VERSION 5.7 ;
  NOWIREEXTENSIONATPIN ON ;
  DIVIDERCHAR "/" ;
  BUSBITCHARS "[]" ;
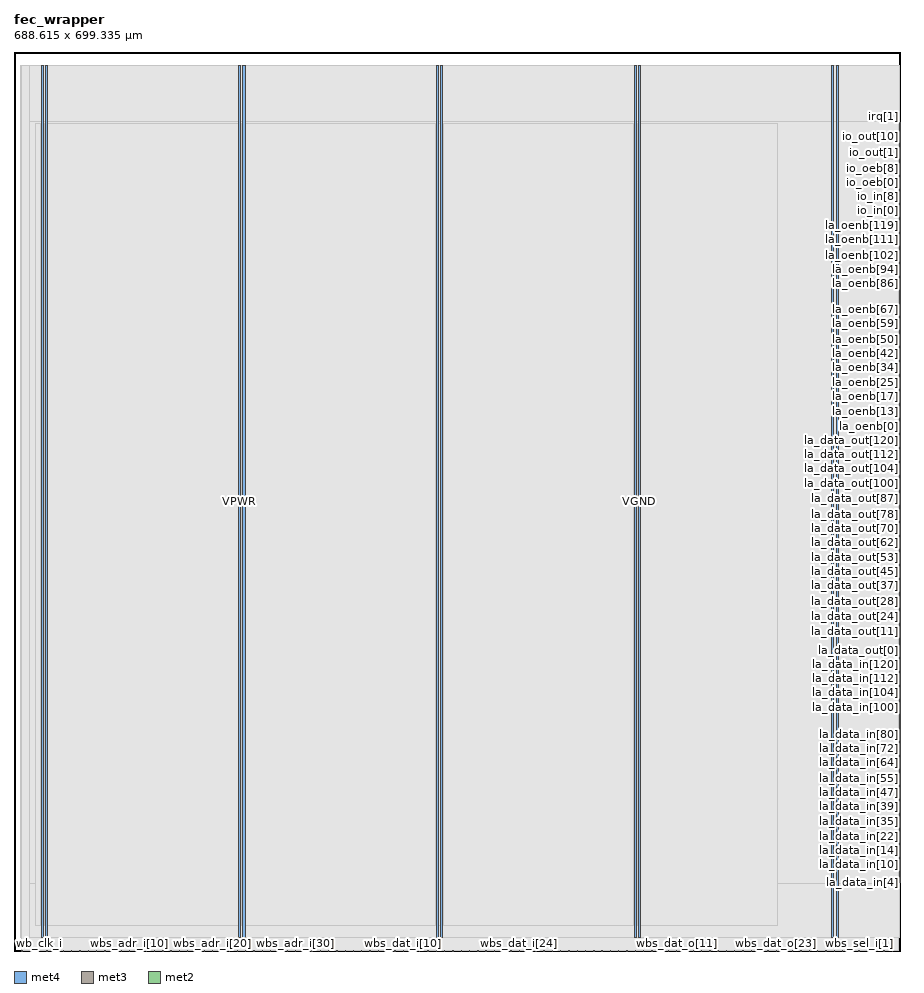
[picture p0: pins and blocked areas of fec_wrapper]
MACRO fec_wrapper
  CLASS BLOCK ;
  FOREIGN fec_wrapper ;
  ORIGIN 0.000 0.000 ;
  SIZE 688.615 BY 699.335 ;
  PIN VGND
    DIRECTION INOUT ;
    USE GROUND ;
    PORT
      LAYER met4 ;
        RECT 24.340 10.640 25.940 688.400 ;
    END
    PORT
      LAYER met4 ;
        RECT 177.940 10.640 179.540 688.400 ;
    END
    PORT
      LAYER met4 ;
        RECT 331.540 10.640 333.140 688.400 ;
    END
    PORT
      LAYER met4 ;
        RECT 485.140 10.640 486.740 688.400 ;
    END
    PORT
      LAYER met4 ;
        RECT 638.740 10.640 640.340 688.400 ;
    END
  END VGND
  PIN VPWR
    DIRECTION INOUT ;
    USE POWER ;
    PORT
      LAYER met4 ;
        RECT 21.040 10.640 22.640 688.400 ;
    END
    PORT
      LAYER met4 ;
        RECT 174.640 10.640 176.240 688.400 ;
    END
    PORT
      LAYER met4 ;
        RECT 328.240 10.640 329.840 688.400 ;
    END
    PORT
      LAYER met4 ;
        RECT 481.840 10.640 483.440 688.400 ;
    END
    PORT
      LAYER met4 ;
        RECT 635.440 10.640 637.040 688.400 ;
    END
  END VPWR
  PIN io_in[0]
    DIRECTION INPUT ;
    USE SIGNAL ;
    ANTENNAGATEAREA 0.647700 ;
    ANTENNADIFFAREA 0.434700 ;
    PORT
      LAYER met3 ;
        RECT 688.015 575.320 688.615 575.920 ;
    END
  END io_in[0]
  PIN io_in[10]
    DIRECTION INPUT ;
    USE SIGNAL ;
    PORT
      LAYER met3 ;
        RECT 688.015 588.920 688.615 589.520 ;
    END
  END io_in[10]
  PIN io_in[11]
    DIRECTION INPUT ;
    USE SIGNAL ;
    PORT
      LAYER met3 ;
        RECT 688.015 590.280 688.615 590.880 ;
    END
  END io_in[11]
  PIN io_in[12]
    DIRECTION INPUT ;
    USE SIGNAL ;
    PORT
      LAYER met3 ;
        RECT 688.015 591.640 688.615 592.240 ;
    END
  END io_in[12]
  PIN io_in[13]
    DIRECTION INPUT ;
    USE SIGNAL ;
    PORT
      LAYER met3 ;
        RECT 688.015 593.000 688.615 593.600 ;
    END
  END io_in[13]
  PIN io_in[14]
    DIRECTION INPUT ;
    USE SIGNAL ;
    PORT
      LAYER met3 ;
        RECT 688.015 594.360 688.615 594.960 ;
    END
  END io_in[14]
  PIN io_in[15]
    DIRECTION INPUT ;
    USE SIGNAL ;
    PORT
      LAYER met3 ;
        RECT 688.015 595.720 688.615 596.320 ;
    END
  END io_in[15]
  PIN io_in[1]
    DIRECTION INPUT ;
    USE SIGNAL ;
    ANTENNAGATEAREA 0.593700 ;
    ANTENNADIFFAREA 0.434700 ;
    PORT
      LAYER met3 ;
        RECT 688.015 576.680 688.615 577.280 ;
    END
  END io_in[1]
  PIN io_in[2]
    DIRECTION INPUT ;
    USE SIGNAL ;
    ANTENNAGATEAREA 0.631200 ;
    ANTENNADIFFAREA 0.434700 ;
    PORT
      LAYER met3 ;
        RECT 688.015 578.040 688.615 578.640 ;
    END
  END io_in[2]
  PIN io_in[3]
    DIRECTION INPUT ;
    USE SIGNAL ;
    PORT
      LAYER met3 ;
        RECT 688.015 579.400 688.615 580.000 ;
    END
  END io_in[3]
  PIN io_in[4]
    DIRECTION INPUT ;
    USE SIGNAL ;
    PORT
      LAYER met3 ;
        RECT 688.015 580.760 688.615 581.360 ;
    END
  END io_in[4]
  PIN io_in[5]
    DIRECTION INPUT ;
    USE SIGNAL ;
    PORT
      LAYER met3 ;
        RECT 688.015 582.120 688.615 582.720 ;
    END
  END io_in[5]
  PIN io_in[6]
    DIRECTION INPUT ;
    USE SIGNAL ;
    PORT
      LAYER met3 ;
        RECT 688.015 583.480 688.615 584.080 ;
    END
  END io_in[6]
  PIN io_in[7]
    DIRECTION INPUT ;
    USE SIGNAL ;
    PORT
      LAYER met3 ;
        RECT 688.015 584.840 688.615 585.440 ;
    END
  END io_in[7]
  PIN io_in[8]
    DIRECTION INPUT ;
    USE SIGNAL ;
    PORT
      LAYER met3 ;
        RECT 688.015 586.200 688.615 586.800 ;
    END
  END io_in[8]
  PIN io_in[9]
    DIRECTION INPUT ;
    USE SIGNAL ;
    PORT
      LAYER met3 ;
        RECT 688.015 587.560 688.615 588.160 ;
    END
  END io_in[9]
  PIN io_oeb[0]
    DIRECTION OUTPUT ;
    USE SIGNAL ;
    PORT
      LAYER met3 ;
        RECT 688.015 597.080 688.615 597.680 ;
    END
  END io_oeb[0]
  PIN io_oeb[10]
    DIRECTION OUTPUT ;
    USE SIGNAL ;
    PORT
      LAYER met3 ;
        RECT 688.015 610.680 688.615 611.280 ;
    END
  END io_oeb[10]
  PIN io_oeb[11]
    DIRECTION OUTPUT ;
    USE SIGNAL ;
    PORT
      LAYER met3 ;
        RECT 688.015 612.040 688.615 612.640 ;
    END
  END io_oeb[11]
  PIN io_oeb[12]
    DIRECTION OUTPUT ;
    USE SIGNAL ;
    PORT
      LAYER met3 ;
        RECT 688.015 613.400 688.615 614.000 ;
    END
  END io_oeb[12]
  PIN io_oeb[13]
    DIRECTION OUTPUT ;
    USE SIGNAL ;
    PORT
      LAYER met3 ;
        RECT 688.015 614.760 688.615 615.360 ;
    END
  END io_oeb[13]
  PIN io_oeb[14]
    DIRECTION OUTPUT ;
    USE SIGNAL ;
    PORT
      LAYER met3 ;
        RECT 688.015 616.120 688.615 616.720 ;
    END
  END io_oeb[14]
  PIN io_oeb[15]
    DIRECTION OUTPUT ;
    USE SIGNAL ;
    PORT
      LAYER met3 ;
        RECT 688.015 617.480 688.615 618.080 ;
    END
  END io_oeb[15]
  PIN io_oeb[1]
    DIRECTION OUTPUT ;
    USE SIGNAL ;
    PORT
      LAYER met3 ;
        RECT 688.015 598.440 688.615 599.040 ;
    END
  END io_oeb[1]
  PIN io_oeb[2]
    DIRECTION OUTPUT ;
    USE SIGNAL ;
    PORT
      LAYER met3 ;
        RECT 688.015 599.800 688.615 600.400 ;
    END
  END io_oeb[2]
  PIN io_oeb[3]
    DIRECTION OUTPUT ;
    USE SIGNAL ;
    PORT
      LAYER met3 ;
        RECT 688.015 601.160 688.615 601.760 ;
    END
  END io_oeb[3]
  PIN io_oeb[4]
    DIRECTION OUTPUT ;
    USE SIGNAL ;
    PORT
      LAYER met3 ;
        RECT 688.015 602.520 688.615 603.120 ;
    END
  END io_oeb[4]
  PIN io_oeb[5]
    DIRECTION OUTPUT ;
    USE SIGNAL ;
    PORT
      LAYER met3 ;
        RECT 688.015 603.880 688.615 604.480 ;
    END
  END io_oeb[5]
  PIN io_oeb[6]
    DIRECTION OUTPUT ;
    USE SIGNAL ;
    PORT
      LAYER met3 ;
        RECT 688.015 605.240 688.615 605.840 ;
    END
  END io_oeb[6]
  PIN io_oeb[7]
    DIRECTION OUTPUT ;
    USE SIGNAL ;
    PORT
      LAYER met3 ;
        RECT 688.015 606.600 688.615 607.200 ;
    END
  END io_oeb[7]
  PIN io_oeb[8]
    DIRECTION OUTPUT ;
    USE SIGNAL ;
    PORT
      LAYER met3 ;
        RECT 688.015 607.960 688.615 608.560 ;
    END
  END io_oeb[8]
  PIN io_oeb[9]
    DIRECTION OUTPUT ;
    USE SIGNAL ;
    PORT
      LAYER met3 ;
        RECT 688.015 609.320 688.615 609.920 ;
    END
  END io_oeb[9]
  PIN io_out[0]
    DIRECTION OUTPUT ;
    USE SIGNAL ;
    ANTENNADIFFAREA 2.673000 ;
    PORT
      LAYER met3 ;
        RECT 688.015 618.840 688.615 619.440 ;
    END
  END io_out[0]
  PIN io_out[10]
    DIRECTION OUTPUT ;
    USE SIGNAL ;
    PORT
      LAYER met3 ;
        RECT 688.015 632.440 688.615 633.040 ;
    END
  END io_out[10]
  PIN io_out[11]
    DIRECTION OUTPUT ;
    USE SIGNAL ;
    PORT
      LAYER met3 ;
        RECT 688.015 633.800 688.615 634.400 ;
    END
  END io_out[11]
  PIN io_out[12]
    DIRECTION OUTPUT ;
    USE SIGNAL ;
    PORT
      LAYER met3 ;
        RECT 688.015 635.160 688.615 635.760 ;
    END
  END io_out[12]
  PIN io_out[13]
    DIRECTION OUTPUT ;
    USE SIGNAL ;
    PORT
      LAYER met3 ;
        RECT 688.015 636.520 688.615 637.120 ;
    END
  END io_out[13]
  PIN io_out[14]
    DIRECTION OUTPUT ;
    USE SIGNAL ;
    PORT
      LAYER met3 ;
        RECT 688.015 637.880 688.615 638.480 ;
    END
  END io_out[14]
  PIN io_out[15]
    DIRECTION OUTPUT ;
    USE SIGNAL ;
    PORT
      LAYER met3 ;
        RECT 688.015 639.240 688.615 639.840 ;
    END
  END io_out[15]
  PIN io_out[1]
    DIRECTION OUTPUT ;
    USE SIGNAL ;
    ANTENNADIFFAREA 2.673000 ;
    PORT
      LAYER met3 ;
        RECT 688.015 620.200 688.615 620.800 ;
    END
  END io_out[1]
  PIN io_out[2]
    DIRECTION OUTPUT ;
    USE SIGNAL ;
    ANTENNADIFFAREA 2.673000 ;
    PORT
      LAYER met3 ;
        RECT 688.015 621.560 688.615 622.160 ;
    END
  END io_out[2]
  PIN io_out[3]
    DIRECTION OUTPUT ;
    USE SIGNAL ;
    ANTENNADIFFAREA 2.673000 ;
    PORT
      LAYER met3 ;
        RECT 688.015 622.920 688.615 623.520 ;
    END
  END io_out[3]
  PIN io_out[4]
    DIRECTION OUTPUT ;
    USE SIGNAL ;
    PORT
      LAYER met3 ;
        RECT 688.015 624.280 688.615 624.880 ;
    END
  END io_out[4]
  PIN io_out[5]
    DIRECTION OUTPUT ;
    USE SIGNAL ;
    PORT
      LAYER met3 ;
        RECT 688.015 625.640 688.615 626.240 ;
    END
  END io_out[5]
  PIN io_out[6]
    DIRECTION OUTPUT ;
    USE SIGNAL ;
    PORT
      LAYER met3 ;
        RECT 688.015 627.000 688.615 627.600 ;
    END
  END io_out[6]
  PIN io_out[7]
    DIRECTION OUTPUT ;
    USE SIGNAL ;
    PORT
      LAYER met3 ;
        RECT 688.015 628.360 688.615 628.960 ;
    END
  END io_out[7]
  PIN io_out[8]
    DIRECTION OUTPUT ;
    USE SIGNAL ;
    PORT
      LAYER met3 ;
        RECT 688.015 629.720 688.615 630.320 ;
    END
  END io_out[8]
  PIN io_out[9]
    DIRECTION OUTPUT ;
    USE SIGNAL ;
    PORT
      LAYER met3 ;
        RECT 688.015 631.080 688.615 631.680 ;
    END
  END io_out[9]
  PIN irq[0]
    DIRECTION OUTPUT ;
    USE SIGNAL ;
    PORT
      LAYER met3 ;
        RECT 688.015 640.600 688.615 641.200 ;
    END
  END irq[0]
  PIN irq[1]
    DIRECTION OUTPUT ;
    USE SIGNAL ;
    PORT
      LAYER met3 ;
        RECT 688.015 641.960 688.615 642.560 ;
    END
  END irq[1]
  PIN irq[2]
    DIRECTION OUTPUT ;
    USE SIGNAL ;
    PORT
      LAYER met3 ;
        RECT 688.015 643.320 688.615 643.920 ;
    END
  END irq[2]
  PIN la_data_in[0]
    DIRECTION INPUT ;
    USE SIGNAL ;
    PORT
      LAYER met3 ;
        RECT 688.015 53.080 688.615 53.680 ;
    END
  END la_data_in[0]
  PIN la_data_in[100]
    DIRECTION INPUT ;
    USE SIGNAL ;
    PORT
      LAYER met3 ;
        RECT 688.015 189.080 688.615 189.680 ;
    END
  END la_data_in[100]
  PIN la_data_in[101]
    DIRECTION INPUT ;
    USE SIGNAL ;
    PORT
      LAYER met3 ;
        RECT 688.015 190.440 688.615 191.040 ;
    END
  END la_data_in[101]
  PIN la_data_in[102]
    DIRECTION INPUT ;
    USE SIGNAL ;
    PORT
      LAYER met3 ;
        RECT 688.015 191.800 688.615 192.400 ;
    END
  END la_data_in[102]
  PIN la_data_in[103]
    DIRECTION INPUT ;
    USE SIGNAL ;
    PORT
      LAYER met3 ;
        RECT 688.015 193.160 688.615 193.760 ;
    END
  END la_data_in[103]
  PIN la_data_in[104]
    DIRECTION INPUT ;
    USE SIGNAL ;
    PORT
      LAYER met3 ;
        RECT 688.015 194.520 688.615 195.120 ;
    END
  END la_data_in[104]
  PIN la_data_in[105]
    DIRECTION INPUT ;
    USE SIGNAL ;
    PORT
      LAYER met3 ;
        RECT 688.015 195.880 688.615 196.480 ;
    END
  END la_data_in[105]
  PIN la_data_in[106]
    DIRECTION INPUT ;
    USE SIGNAL ;
    PORT
      LAYER met3 ;
        RECT 688.015 197.240 688.615 197.840 ;
    END
  END la_data_in[106]
  PIN la_data_in[107]
    DIRECTION INPUT ;
    USE SIGNAL ;
    PORT
      LAYER met3 ;
        RECT 688.015 198.600 688.615 199.200 ;
    END
  END la_data_in[107]
  PIN la_data_in[108]
    DIRECTION INPUT ;
    USE SIGNAL ;
    PORT
      LAYER met3 ;
        RECT 688.015 199.960 688.615 200.560 ;
    END
  END la_data_in[108]
  PIN la_data_in[109]
    DIRECTION INPUT ;
    USE SIGNAL ;
    PORT
      LAYER met3 ;
        RECT 688.015 201.320 688.615 201.920 ;
    END
  END la_data_in[109]
  PIN la_data_in[10]
    DIRECTION INPUT ;
    USE SIGNAL ;
    PORT
      LAYER met3 ;
        RECT 688.015 66.680 688.615 67.280 ;
    END
  END la_data_in[10]
  PIN la_data_in[110]
    DIRECTION INPUT ;
    USE SIGNAL ;
    PORT
      LAYER met3 ;
        RECT 688.015 202.680 688.615 203.280 ;
    END
  END la_data_in[110]
  PIN la_data_in[111]
    DIRECTION INPUT ;
    USE SIGNAL ;
    PORT
      LAYER met3 ;
        RECT 688.015 204.040 688.615 204.640 ;
    END
  END la_data_in[111]
  PIN la_data_in[112]
    DIRECTION INPUT ;
    USE SIGNAL ;
    PORT
      LAYER met3 ;
        RECT 688.015 205.400 688.615 206.000 ;
    END
  END la_data_in[112]
  PIN la_data_in[113]
    DIRECTION INPUT ;
    USE SIGNAL ;
    PORT
      LAYER met3 ;
        RECT 688.015 206.760 688.615 207.360 ;
    END
  END la_data_in[113]
  PIN la_data_in[114]
    DIRECTION INPUT ;
    USE SIGNAL ;
    PORT
      LAYER met3 ;
        RECT 688.015 208.120 688.615 208.720 ;
    END
  END la_data_in[114]
  PIN la_data_in[115]
    DIRECTION INPUT ;
    USE SIGNAL ;
    PORT
      LAYER met3 ;
        RECT 688.015 209.480 688.615 210.080 ;
    END
  END la_data_in[115]
  PIN la_data_in[116]
    DIRECTION INPUT ;
    USE SIGNAL ;
    PORT
      LAYER met3 ;
        RECT 688.015 210.840 688.615 211.440 ;
    END
  END la_data_in[116]
  PIN la_data_in[117]
    DIRECTION INPUT ;
    USE SIGNAL ;
    PORT
      LAYER met3 ;
        RECT 688.015 212.200 688.615 212.800 ;
    END
  END la_data_in[117]
  PIN la_data_in[118]
    DIRECTION INPUT ;
    USE SIGNAL ;
    PORT
      LAYER met3 ;
        RECT 688.015 213.560 688.615 214.160 ;
    END
  END la_data_in[118]
  PIN la_data_in[119]
    DIRECTION INPUT ;
    USE SIGNAL ;
    PORT
      LAYER met3 ;
        RECT 688.015 214.920 688.615 215.520 ;
    END
  END la_data_in[119]
  PIN la_data_in[11]
    DIRECTION INPUT ;
    USE SIGNAL ;
    PORT
      LAYER met3 ;
        RECT 688.015 68.040 688.615 68.640 ;
    END
  END la_data_in[11]
  PIN la_data_in[120]
    DIRECTION INPUT ;
    USE SIGNAL ;
    PORT
      LAYER met3 ;
        RECT 688.015 216.280 688.615 216.880 ;
    END
  END la_data_in[120]
  PIN la_data_in[121]
    DIRECTION INPUT ;
    USE SIGNAL ;
    PORT
      LAYER met3 ;
        RECT 688.015 217.640 688.615 218.240 ;
    END
  END la_data_in[121]
  PIN la_data_in[122]
    DIRECTION INPUT ;
    USE SIGNAL ;
    PORT
      LAYER met3 ;
        RECT 688.015 219.000 688.615 219.600 ;
    END
  END la_data_in[122]
  PIN la_data_in[123]
    DIRECTION INPUT ;
    USE SIGNAL ;
    PORT
      LAYER met3 ;
        RECT 688.015 220.360 688.615 220.960 ;
    END
  END la_data_in[123]
  PIN la_data_in[124]
    DIRECTION INPUT ;
    USE SIGNAL ;
    PORT
      LAYER met3 ;
        RECT 688.015 221.720 688.615 222.320 ;
    END
  END la_data_in[124]
  PIN la_data_in[125]
    DIRECTION INPUT ;
    USE SIGNAL ;
    PORT
      LAYER met3 ;
        RECT 688.015 223.080 688.615 223.680 ;
    END
  END la_data_in[125]
  PIN la_data_in[126]
    DIRECTION INPUT ;
    USE SIGNAL ;
    PORT
      LAYER met3 ;
        RECT 688.015 224.440 688.615 225.040 ;
    END
  END la_data_in[126]
  PIN la_data_in[127]
    DIRECTION INPUT ;
    USE SIGNAL ;
    PORT
      LAYER met3 ;
        RECT 688.015 225.800 688.615 226.400 ;
    END
  END la_data_in[127]
  PIN la_data_in[12]
    DIRECTION INPUT ;
    USE SIGNAL ;
    PORT
      LAYER met3 ;
        RECT 688.015 69.400 688.615 70.000 ;
    END
  END la_data_in[12]
  PIN la_data_in[13]
    DIRECTION INPUT ;
    USE SIGNAL ;
    PORT
      LAYER met3 ;
        RECT 688.015 70.760 688.615 71.360 ;
    END
  END la_data_in[13]
  PIN la_data_in[14]
    DIRECTION INPUT ;
    USE SIGNAL ;
    PORT
      LAYER met3 ;
        RECT 688.015 72.120 688.615 72.720 ;
    END
  END la_data_in[14]
  PIN la_data_in[15]
    DIRECTION INPUT ;
    USE SIGNAL ;
    PORT
      LAYER met3 ;
        RECT 688.015 73.480 688.615 74.080 ;
    END
  END la_data_in[15]
  PIN la_data_in[16]
    DIRECTION INPUT ;
    USE SIGNAL ;
    PORT
      LAYER met3 ;
        RECT 688.015 74.840 688.615 75.440 ;
    END
  END la_data_in[16]
  PIN la_data_in[17]
    DIRECTION INPUT ;
    USE SIGNAL ;
    PORT
      LAYER met3 ;
        RECT 688.015 76.200 688.615 76.800 ;
    END
  END la_data_in[17]
  PIN la_data_in[18]
    DIRECTION INPUT ;
    USE SIGNAL ;
    PORT
      LAYER met3 ;
        RECT 688.015 77.560 688.615 78.160 ;
    END
  END la_data_in[18]
  PIN la_data_in[19]
    DIRECTION INPUT ;
    USE SIGNAL ;
    PORT
      LAYER met3 ;
        RECT 688.015 78.920 688.615 79.520 ;
    END
  END la_data_in[19]
  PIN la_data_in[1]
    DIRECTION INPUT ;
    USE SIGNAL ;
    PORT
      LAYER met3 ;
        RECT 688.015 54.440 688.615 55.040 ;
    END
  END la_data_in[1]
  PIN la_data_in[20]
    DIRECTION INPUT ;
    USE SIGNAL ;
    PORT
      LAYER met3 ;
        RECT 688.015 80.280 688.615 80.880 ;
    END
  END la_data_in[20]
  PIN la_data_in[21]
    DIRECTION INPUT ;
    USE SIGNAL ;
    PORT
      LAYER met3 ;
        RECT 688.015 81.640 688.615 82.240 ;
    END
  END la_data_in[21]
  PIN la_data_in[22]
    DIRECTION INPUT ;
    USE SIGNAL ;
    PORT
      LAYER met3 ;
        RECT 688.015 83.000 688.615 83.600 ;
    END
  END la_data_in[22]
  PIN la_data_in[23]
    DIRECTION INPUT ;
    USE SIGNAL ;
    PORT
      LAYER met3 ;
        RECT 688.015 84.360 688.615 84.960 ;
    END
  END la_data_in[23]
  PIN la_data_in[24]
    DIRECTION INPUT ;
    USE SIGNAL ;
    PORT
      LAYER met3 ;
        RECT 688.015 85.720 688.615 86.320 ;
    END
  END la_data_in[24]
  PIN la_data_in[25]
    DIRECTION INPUT ;
    USE SIGNAL ;
    PORT
      LAYER met3 ;
        RECT 688.015 87.080 688.615 87.680 ;
    END
  END la_data_in[25]
  PIN la_data_in[26]
    DIRECTION INPUT ;
    USE SIGNAL ;
    PORT
      LAYER met3 ;
        RECT 688.015 88.440 688.615 89.040 ;
    END
  END la_data_in[26]
  PIN la_data_in[27]
    DIRECTION INPUT ;
    USE SIGNAL ;
    PORT
      LAYER met3 ;
        RECT 688.015 89.800 688.615 90.400 ;
    END
  END la_data_in[27]
  PIN la_data_in[28]
    DIRECTION INPUT ;
    USE SIGNAL ;
    PORT
      LAYER met3 ;
        RECT 688.015 91.160 688.615 91.760 ;
    END
  END la_data_in[28]
  PIN la_data_in[29]
    DIRECTION INPUT ;
    USE SIGNAL ;
    PORT
      LAYER met3 ;
        RECT 688.015 92.520 688.615 93.120 ;
    END
  END la_data_in[29]
  PIN la_data_in[2]
    DIRECTION INPUT ;
    USE SIGNAL ;
    PORT
      LAYER met3 ;
        RECT 688.015 55.800 688.615 56.400 ;
    END
  END la_data_in[2]
  PIN la_data_in[30]
    DIRECTION INPUT ;
    USE SIGNAL ;
    PORT
      LAYER met3 ;
        RECT 688.015 93.880 688.615 94.480 ;
    END
  END la_data_in[30]
  PIN la_data_in[31]
    DIRECTION INPUT ;
    USE SIGNAL ;
    PORT
      LAYER met3 ;
        RECT 688.015 95.240 688.615 95.840 ;
    END
  END la_data_in[31]
  PIN la_data_in[32]
    DIRECTION INPUT ;
    USE SIGNAL ;
    PORT
      LAYER met3 ;
        RECT 688.015 96.600 688.615 97.200 ;
    END
  END la_data_in[32]
  PIN la_data_in[33]
    DIRECTION INPUT ;
    USE SIGNAL ;
    PORT
      LAYER met3 ;
        RECT 688.015 97.960 688.615 98.560 ;
    END
  END la_data_in[33]
  PIN la_data_in[34]
    DIRECTION INPUT ;
    USE SIGNAL ;
    PORT
      LAYER met3 ;
        RECT 688.015 99.320 688.615 99.920 ;
    END
  END la_data_in[34]
  PIN la_data_in[35]
    DIRECTION INPUT ;
    USE SIGNAL ;
    PORT
      LAYER met3 ;
        RECT 688.015 100.680 688.615 101.280 ;
    END
  END la_data_in[35]
  PIN la_data_in[36]
    DIRECTION INPUT ;
    USE SIGNAL ;
    PORT
      LAYER met3 ;
        RECT 688.015 102.040 688.615 102.640 ;
    END
  END la_data_in[36]
  PIN la_data_in[37]
    DIRECTION INPUT ;
    USE SIGNAL ;
    PORT
      LAYER met3 ;
        RECT 688.015 103.400 688.615 104.000 ;
    END
  END la_data_in[37]
  PIN la_data_in[38]
    DIRECTION INPUT ;
    USE SIGNAL ;
    PORT
      LAYER met3 ;
        RECT 688.015 104.760 688.615 105.360 ;
    END
  END la_data_in[38]
  PIN la_data_in[39]
    DIRECTION INPUT ;
    USE SIGNAL ;
    PORT
      LAYER met3 ;
        RECT 688.015 106.120 688.615 106.720 ;
    END
  END la_data_in[39]
  PIN la_data_in[3]
    DIRECTION INPUT ;
    USE SIGNAL ;
    PORT
      LAYER met3 ;
        RECT 688.015 57.160 688.615 57.760 ;
    END
  END la_data_in[3]
  PIN la_data_in[40]
    DIRECTION INPUT ;
    USE SIGNAL ;
    PORT
      LAYER met3 ;
        RECT 688.015 107.480 688.615 108.080 ;
    END
  END la_data_in[40]
  PIN la_data_in[41]
    DIRECTION INPUT ;
    USE SIGNAL ;
    PORT
      LAYER met3 ;
        RECT 688.015 108.840 688.615 109.440 ;
    END
  END la_data_in[41]
  PIN la_data_in[42]
    DIRECTION INPUT ;
    USE SIGNAL ;
    PORT
      LAYER met3 ;
        RECT 688.015 110.200 688.615 110.800 ;
    END
  END la_data_in[42]
  PIN la_data_in[43]
    DIRECTION INPUT ;
    USE SIGNAL ;
    PORT
      LAYER met3 ;
        RECT 688.015 111.560 688.615 112.160 ;
    END
  END la_data_in[43]
  PIN la_data_in[44]
    DIRECTION INPUT ;
    USE SIGNAL ;
    PORT
      LAYER met3 ;
        RECT 688.015 112.920 688.615 113.520 ;
    END
  END la_data_in[44]
  PIN la_data_in[45]
    DIRECTION INPUT ;
    USE SIGNAL ;
    PORT
      LAYER met3 ;
        RECT 688.015 114.280 688.615 114.880 ;
    END
  END la_data_in[45]
  PIN la_data_in[46]
    DIRECTION INPUT ;
    USE SIGNAL ;
    PORT
      LAYER met3 ;
        RECT 688.015 115.640 688.615 116.240 ;
    END
  END la_data_in[46]
  PIN la_data_in[47]
    DIRECTION INPUT ;
    USE SIGNAL ;
    PORT
      LAYER met3 ;
        RECT 688.015 117.000 688.615 117.600 ;
    END
  END la_data_in[47]
  PIN la_data_in[48]
    DIRECTION INPUT ;
    USE SIGNAL ;
    PORT
      LAYER met3 ;
        RECT 688.015 118.360 688.615 118.960 ;
    END
  END la_data_in[48]
  PIN la_data_in[49]
    DIRECTION INPUT ;
    USE SIGNAL ;
    PORT
      LAYER met3 ;
        RECT 688.015 119.720 688.615 120.320 ;
    END
  END la_data_in[49]
  PIN la_data_in[4]
    DIRECTION INPUT ;
    USE SIGNAL ;
    PORT
      LAYER met3 ;
        RECT 688.015 58.520 688.615 59.120 ;
    END
  END la_data_in[4]
  PIN la_data_in[50]
    DIRECTION INPUT ;
    USE SIGNAL ;
    PORT
      LAYER met3 ;
        RECT 688.015 121.080 688.615 121.680 ;
    END
  END la_data_in[50]
  PIN la_data_in[51]
    DIRECTION INPUT ;
    USE SIGNAL ;
    PORT
      LAYER met3 ;
        RECT 688.015 122.440 688.615 123.040 ;
    END
  END la_data_in[51]
  PIN la_data_in[52]
    DIRECTION INPUT ;
    USE SIGNAL ;
    PORT
      LAYER met3 ;
        RECT 688.015 123.800 688.615 124.400 ;
    END
  END la_data_in[52]
  PIN la_data_in[53]
    DIRECTION INPUT ;
    USE SIGNAL ;
    PORT
      LAYER met3 ;
        RECT 688.015 125.160 688.615 125.760 ;
    END
  END la_data_in[53]
  PIN la_data_in[54]
    DIRECTION INPUT ;
    USE SIGNAL ;
    PORT
      LAYER met3 ;
        RECT 688.015 126.520 688.615 127.120 ;
    END
  END la_data_in[54]
  PIN la_data_in[55]
    DIRECTION INPUT ;
    USE SIGNAL ;
    PORT
      LAYER met3 ;
        RECT 688.015 127.880 688.615 128.480 ;
    END
  END la_data_in[55]
  PIN la_data_in[56]
    DIRECTION INPUT ;
    USE SIGNAL ;
    PORT
      LAYER met3 ;
        RECT 688.015 129.240 688.615 129.840 ;
    END
  END la_data_in[56]
  PIN la_data_in[57]
    DIRECTION INPUT ;
    USE SIGNAL ;
    PORT
      LAYER met3 ;
        RECT 688.015 130.600 688.615 131.200 ;
    END
  END la_data_in[57]
  PIN la_data_in[58]
    DIRECTION INPUT ;
    USE SIGNAL ;
    PORT
      LAYER met3 ;
        RECT 688.015 131.960 688.615 132.560 ;
    END
  END la_data_in[58]
  PIN la_data_in[59]
    DIRECTION INPUT ;
    USE SIGNAL ;
    PORT
      LAYER met3 ;
        RECT 688.015 133.320 688.615 133.920 ;
    END
  END la_data_in[59]
  PIN la_data_in[5]
    DIRECTION INPUT ;
    USE SIGNAL ;
    PORT
      LAYER met3 ;
        RECT 688.015 59.880 688.615 60.480 ;
    END
  END la_data_in[5]
  PIN la_data_in[60]
    DIRECTION INPUT ;
    USE SIGNAL ;
    PORT
      LAYER met3 ;
        RECT 688.015 134.680 688.615 135.280 ;
    END
  END la_data_in[60]
  PIN la_data_in[61]
    DIRECTION INPUT ;
    USE SIGNAL ;
    PORT
      LAYER met3 ;
        RECT 688.015 136.040 688.615 136.640 ;
    END
  END la_data_in[61]
  PIN la_data_in[62]
    DIRECTION INPUT ;
    USE SIGNAL ;
    PORT
      LAYER met3 ;
        RECT 688.015 137.400 688.615 138.000 ;
    END
  END la_data_in[62]
  PIN la_data_in[63]
    DIRECTION INPUT ;
    USE SIGNAL ;
    PORT
      LAYER met3 ;
        RECT 688.015 138.760 688.615 139.360 ;
    END
  END la_data_in[63]
  PIN la_data_in[64]
    DIRECTION INPUT ;
    USE SIGNAL ;
    ANTENNAGATEAREA 0.647700 ;
    ANTENNADIFFAREA 0.434700 ;
    PORT
      LAYER met3 ;
        RECT 688.015 140.120 688.615 140.720 ;
    END
  END la_data_in[64]
  PIN la_data_in[65]
    DIRECTION INPUT ;
    USE SIGNAL ;
    ANTENNAGATEAREA 0.647700 ;
    ANTENNADIFFAREA 0.434700 ;
    PORT
      LAYER met3 ;
        RECT 688.015 141.480 688.615 142.080 ;
    END
  END la_data_in[65]
  PIN la_data_in[66]
    DIRECTION INPUT ;
    USE SIGNAL ;
    PORT
      LAYER met3 ;
        RECT 688.015 142.840 688.615 143.440 ;
    END
  END la_data_in[66]
  PIN la_data_in[67]
    DIRECTION INPUT ;
    USE SIGNAL ;
    PORT
      LAYER met3 ;
        RECT 688.015 144.200 688.615 144.800 ;
    END
  END la_data_in[67]
  PIN la_data_in[68]
    DIRECTION INPUT ;
    USE SIGNAL ;
    PORT
      LAYER met3 ;
        RECT 688.015 145.560 688.615 146.160 ;
    END
  END la_data_in[68]
  PIN la_data_in[69]
    DIRECTION INPUT ;
    USE SIGNAL ;
    PORT
      LAYER met3 ;
        RECT 688.015 146.920 688.615 147.520 ;
    END
  END la_data_in[69]
  PIN la_data_in[6]
    DIRECTION INPUT ;
    USE SIGNAL ;
    PORT
      LAYER met3 ;
        RECT 688.015 61.240 688.615 61.840 ;
    END
  END la_data_in[6]
  PIN la_data_in[70]
    DIRECTION INPUT ;
    USE SIGNAL ;
    PORT
      LAYER met3 ;
        RECT 688.015 148.280 688.615 148.880 ;
    END
  END la_data_in[70]
  PIN la_data_in[71]
    DIRECTION INPUT ;
    USE SIGNAL ;
    PORT
      LAYER met3 ;
        RECT 688.015 149.640 688.615 150.240 ;
    END
  END la_data_in[71]
  PIN la_data_in[72]
    DIRECTION INPUT ;
    USE SIGNAL ;
    PORT
      LAYER met3 ;
        RECT 688.015 151.000 688.615 151.600 ;
    END
  END la_data_in[72]
  PIN la_data_in[73]
    DIRECTION INPUT ;
    USE SIGNAL ;
    PORT
      LAYER met3 ;
        RECT 688.015 152.360 688.615 152.960 ;
    END
  END la_data_in[73]
  PIN la_data_in[74]
    DIRECTION INPUT ;
    USE SIGNAL ;
    PORT
      LAYER met3 ;
        RECT 688.015 153.720 688.615 154.320 ;
    END
  END la_data_in[74]
  PIN la_data_in[75]
    DIRECTION INPUT ;
    USE SIGNAL ;
    PORT
      LAYER met3 ;
        RECT 688.015 155.080 688.615 155.680 ;
    END
  END la_data_in[75]
  PIN la_data_in[76]
    DIRECTION INPUT ;
    USE SIGNAL ;
    PORT
      LAYER met3 ;
        RECT 688.015 156.440 688.615 157.040 ;
    END
  END la_data_in[76]
  PIN la_data_in[77]
    DIRECTION INPUT ;
    USE SIGNAL ;
    PORT
      LAYER met3 ;
        RECT 688.015 157.800 688.615 158.400 ;
    END
  END la_data_in[77]
  PIN la_data_in[78]
    DIRECTION INPUT ;
    USE SIGNAL ;
    PORT
      LAYER met3 ;
        RECT 688.015 159.160 688.615 159.760 ;
    END
  END la_data_in[78]
  PIN la_data_in[79]
    DIRECTION INPUT ;
    USE SIGNAL ;
    PORT
      LAYER met3 ;
        RECT 688.015 160.520 688.615 161.120 ;
    END
  END la_data_in[79]
  PIN la_data_in[7]
    DIRECTION INPUT ;
    USE SIGNAL ;
    PORT
      LAYER met3 ;
        RECT 688.015 62.600 688.615 63.200 ;
    END
  END la_data_in[7]
  PIN la_data_in[80]
    DIRECTION INPUT ;
    USE SIGNAL ;
    PORT
      LAYER met3 ;
        RECT 688.015 161.880 688.615 162.480 ;
    END
  END la_data_in[80]
  PIN la_data_in[81]
    DIRECTION INPUT ;
    USE SIGNAL ;
    PORT
      LAYER met3 ;
        RECT 688.015 163.240 688.615 163.840 ;
    END
  END la_data_in[81]
  PIN la_data_in[82]
    DIRECTION INPUT ;
    USE SIGNAL ;
    PORT
      LAYER met3 ;
        RECT 688.015 164.600 688.615 165.200 ;
    END
  END la_data_in[82]
  PIN la_data_in[83]
    DIRECTION INPUT ;
    USE SIGNAL ;
    PORT
      LAYER met3 ;
        RECT 688.015 165.960 688.615 166.560 ;
    END
  END la_data_in[83]
  PIN la_data_in[84]
    DIRECTION INPUT ;
    USE SIGNAL ;
    PORT
      LAYER met3 ;
        RECT 688.015 167.320 688.615 167.920 ;
    END
  END la_data_in[84]
  PIN la_data_in[85]
    DIRECTION INPUT ;
    USE SIGNAL ;
    PORT
      LAYER met3 ;
        RECT 688.015 168.680 688.615 169.280 ;
    END
  END la_data_in[85]
  PIN la_data_in[86]
    DIRECTION INPUT ;
    USE SIGNAL ;
    PORT
      LAYER met3 ;
        RECT 688.015 170.040 688.615 170.640 ;
    END
  END la_data_in[86]
  PIN la_data_in[87]
    DIRECTION INPUT ;
    USE SIGNAL ;
    PORT
      LAYER met3 ;
        RECT 688.015 171.400 688.615 172.000 ;
    END
  END la_data_in[87]
  PIN la_data_in[88]
    DIRECTION INPUT ;
    USE SIGNAL ;
    PORT
      LAYER met3 ;
        RECT 688.015 172.760 688.615 173.360 ;
    END
  END la_data_in[88]
  PIN la_data_in[89]
    DIRECTION INPUT ;
    USE SIGNAL ;
    PORT
      LAYER met3 ;
        RECT 688.015 174.120 688.615 174.720 ;
    END
  END la_data_in[89]
  PIN la_data_in[8]
    DIRECTION INPUT ;
    USE SIGNAL ;
    PORT
      LAYER met3 ;
        RECT 688.015 63.960 688.615 64.560 ;
    END
  END la_data_in[8]
  PIN la_data_in[90]
    DIRECTION INPUT ;
    USE SIGNAL ;
    PORT
      LAYER met3 ;
        RECT 688.015 175.480 688.615 176.080 ;
    END
  END la_data_in[90]
  PIN la_data_in[91]
    DIRECTION INPUT ;
    USE SIGNAL ;
    PORT
      LAYER met3 ;
        RECT 688.015 176.840 688.615 177.440 ;
    END
  END la_data_in[91]
  PIN la_data_in[92]
    DIRECTION INPUT ;
    USE SIGNAL ;
    PORT
      LAYER met3 ;
        RECT 688.015 178.200 688.615 178.800 ;
    END
  END la_data_in[92]
  PIN la_data_in[93]
    DIRECTION INPUT ;
    USE SIGNAL ;
    PORT
      LAYER met3 ;
        RECT 688.015 179.560 688.615 180.160 ;
    END
  END la_data_in[93]
  PIN la_data_in[94]
    DIRECTION INPUT ;
    USE SIGNAL ;
    PORT
      LAYER met3 ;
        RECT 688.015 180.920 688.615 181.520 ;
    END
  END la_data_in[94]
  PIN la_data_in[95]
    DIRECTION INPUT ;
    USE SIGNAL ;
    PORT
      LAYER met3 ;
        RECT 688.015 182.280 688.615 182.880 ;
    END
  END la_data_in[95]
  PIN la_data_in[96]
    DIRECTION INPUT ;
    USE SIGNAL ;
    PORT
      LAYER met3 ;
        RECT 688.015 183.640 688.615 184.240 ;
    END
  END la_data_in[96]
  PIN la_data_in[97]
    DIRECTION INPUT ;
    USE SIGNAL ;
    PORT
      LAYER met3 ;
        RECT 688.015 185.000 688.615 185.600 ;
    END
  END la_data_in[97]
  PIN la_data_in[98]
    DIRECTION INPUT ;
    USE SIGNAL ;
    PORT
      LAYER met3 ;
        RECT 688.015 186.360 688.615 186.960 ;
    END
  END la_data_in[98]
  PIN la_data_in[99]
    DIRECTION INPUT ;
    USE SIGNAL ;
    PORT
      LAYER met3 ;
        RECT 688.015 187.720 688.615 188.320 ;
    END
  END la_data_in[99]
  PIN la_data_in[9]
    DIRECTION INPUT ;
    USE SIGNAL ;
    PORT
      LAYER met3 ;
        RECT 688.015 65.320 688.615 65.920 ;
    END
  END la_data_in[9]
  PIN la_data_out[0]
    DIRECTION OUTPUT ;
    USE SIGNAL ;
    PORT
      LAYER met3 ;
        RECT 688.015 227.160 688.615 227.760 ;
    END
  END la_data_out[0]
  PIN la_data_out[100]
    DIRECTION OUTPUT ;
    USE SIGNAL ;
    PORT
      LAYER met3 ;
        RECT 688.015 363.160 688.615 363.760 ;
    END
  END la_data_out[100]
  PIN la_data_out[101]
    DIRECTION OUTPUT ;
    USE SIGNAL ;
    PORT
      LAYER met3 ;
        RECT 688.015 364.520 688.615 365.120 ;
    END
  END la_data_out[101]
  PIN la_data_out[102]
    DIRECTION OUTPUT ;
    USE SIGNAL ;
    PORT
      LAYER met3 ;
        RECT 688.015 365.880 688.615 366.480 ;
    END
  END la_data_out[102]
  PIN la_data_out[103]
    DIRECTION OUTPUT ;
    USE SIGNAL ;
    PORT
      LAYER met3 ;
        RECT 688.015 367.240 688.615 367.840 ;
    END
  END la_data_out[103]
  PIN la_data_out[104]
    DIRECTION OUTPUT ;
    USE SIGNAL ;
    PORT
      LAYER met3 ;
        RECT 688.015 368.600 688.615 369.200 ;
    END
  END la_data_out[104]
  PIN la_data_out[105]
    DIRECTION OUTPUT ;
    USE SIGNAL ;
    PORT
      LAYER met3 ;
        RECT 688.015 369.960 688.615 370.560 ;
    END
  END la_data_out[105]
  PIN la_data_out[106]
    DIRECTION OUTPUT ;
    USE SIGNAL ;
    PORT
      LAYER met3 ;
        RECT 688.015 371.320 688.615 371.920 ;
    END
  END la_data_out[106]
  PIN la_data_out[107]
    DIRECTION OUTPUT ;
    USE SIGNAL ;
    PORT
      LAYER met3 ;
        RECT 688.015 372.680 688.615 373.280 ;
    END
  END la_data_out[107]
  PIN la_data_out[108]
    DIRECTION OUTPUT ;
    USE SIGNAL ;
    PORT
      LAYER met3 ;
        RECT 688.015 374.040 688.615 374.640 ;
    END
  END la_data_out[108]
  PIN la_data_out[109]
    DIRECTION OUTPUT ;
    USE SIGNAL ;
    PORT
      LAYER met3 ;
        RECT 688.015 375.400 688.615 376.000 ;
    END
  END la_data_out[109]
  PIN la_data_out[10]
    DIRECTION OUTPUT ;
    USE SIGNAL ;
    PORT
      LAYER met3 ;
        RECT 688.015 240.760 688.615 241.360 ;
    END
  END la_data_out[10]
  PIN la_data_out[110]
    DIRECTION OUTPUT ;
    USE SIGNAL ;
    PORT
      LAYER met3 ;
        RECT 688.015 376.760 688.615 377.360 ;
    END
  END la_data_out[110]
  PIN la_data_out[111]
    DIRECTION OUTPUT ;
    USE SIGNAL ;
    PORT
      LAYER met3 ;
        RECT 688.015 378.120 688.615 378.720 ;
    END
  END la_data_out[111]
  PIN la_data_out[112]
    DIRECTION OUTPUT ;
    USE SIGNAL ;
    PORT
      LAYER met3 ;
        RECT 688.015 379.480 688.615 380.080 ;
    END
  END la_data_out[112]
  PIN la_data_out[113]
    DIRECTION OUTPUT ;
    USE SIGNAL ;
    PORT
      LAYER met3 ;
        RECT 688.015 380.840 688.615 381.440 ;
    END
  END la_data_out[113]
  PIN la_data_out[114]
    DIRECTION OUTPUT ;
    USE SIGNAL ;
    PORT
      LAYER met3 ;
        RECT 688.015 382.200 688.615 382.800 ;
    END
  END la_data_out[114]
  PIN la_data_out[115]
    DIRECTION OUTPUT ;
    USE SIGNAL ;
    PORT
      LAYER met3 ;
        RECT 688.015 383.560 688.615 384.160 ;
    END
  END la_data_out[115]
  PIN la_data_out[116]
    DIRECTION OUTPUT ;
    USE SIGNAL ;
    PORT
      LAYER met3 ;
        RECT 688.015 384.920 688.615 385.520 ;
    END
  END la_data_out[116]
  PIN la_data_out[117]
    DIRECTION OUTPUT ;
    USE SIGNAL ;
    PORT
      LAYER met3 ;
        RECT 688.015 386.280 688.615 386.880 ;
    END
  END la_data_out[117]
  PIN la_data_out[118]
    DIRECTION OUTPUT ;
    USE SIGNAL ;
    PORT
      LAYER met3 ;
        RECT 688.015 387.640 688.615 388.240 ;
    END
  END la_data_out[118]
  PIN la_data_out[119]
    DIRECTION OUTPUT ;
    USE SIGNAL ;
    PORT
      LAYER met3 ;
        RECT 688.015 389.000 688.615 389.600 ;
    END
  END la_data_out[119]
  PIN la_data_out[11]
    DIRECTION OUTPUT ;
    USE SIGNAL ;
    PORT
      LAYER met3 ;
        RECT 688.015 242.120 688.615 242.720 ;
    END
  END la_data_out[11]
  PIN la_data_out[120]
    DIRECTION OUTPUT ;
    USE SIGNAL ;
    PORT
      LAYER met3 ;
        RECT 688.015 390.360 688.615 390.960 ;
    END
  END la_data_out[120]
  PIN la_data_out[121]
    DIRECTION OUTPUT ;
    USE SIGNAL ;
    PORT
      LAYER met3 ;
        RECT 688.015 391.720 688.615 392.320 ;
    END
  END la_data_out[121]
  PIN la_data_out[122]
    DIRECTION OUTPUT ;
    USE SIGNAL ;
    PORT
      LAYER met3 ;
        RECT 688.015 393.080 688.615 393.680 ;
    END
  END la_data_out[122]
  PIN la_data_out[123]
    DIRECTION OUTPUT ;
    USE SIGNAL ;
    PORT
      LAYER met3 ;
        RECT 688.015 394.440 688.615 395.040 ;
    END
  END la_data_out[123]
  PIN la_data_out[124]
    DIRECTION OUTPUT ;
    USE SIGNAL ;
    PORT
      LAYER met3 ;
        RECT 688.015 395.800 688.615 396.400 ;
    END
  END la_data_out[124]
  PIN la_data_out[125]
    DIRECTION OUTPUT ;
    USE SIGNAL ;
    PORT
      LAYER met3 ;
        RECT 688.015 397.160 688.615 397.760 ;
    END
  END la_data_out[125]
  PIN la_data_out[126]
    DIRECTION OUTPUT ;
    USE SIGNAL ;
    PORT
      LAYER met3 ;
        RECT 688.015 398.520 688.615 399.120 ;
    END
  END la_data_out[126]
  PIN la_data_out[127]
    DIRECTION OUTPUT ;
    USE SIGNAL ;
    PORT
      LAYER met3 ;
        RECT 688.015 399.880 688.615 400.480 ;
    END
  END la_data_out[127]
  PIN la_data_out[12]
    DIRECTION OUTPUT ;
    USE SIGNAL ;
    PORT
      LAYER met3 ;
        RECT 688.015 243.480 688.615 244.080 ;
    END
  END la_data_out[12]
  PIN la_data_out[13]
    DIRECTION OUTPUT ;
    USE SIGNAL ;
    PORT
      LAYER met3 ;
        RECT 688.015 244.840 688.615 245.440 ;
    END
  END la_data_out[13]
  PIN la_data_out[14]
    DIRECTION OUTPUT ;
    USE SIGNAL ;
    PORT
      LAYER met3 ;
        RECT 688.015 246.200 688.615 246.800 ;
    END
  END la_data_out[14]
  PIN la_data_out[15]
    DIRECTION OUTPUT ;
    USE SIGNAL ;
    PORT
      LAYER met3 ;
        RECT 688.015 247.560 688.615 248.160 ;
    END
  END la_data_out[15]
  PIN la_data_out[16]
    DIRECTION OUTPUT ;
    USE SIGNAL ;
    PORT
      LAYER met3 ;
        RECT 688.015 248.920 688.615 249.520 ;
    END
  END la_data_out[16]
  PIN la_data_out[17]
    DIRECTION OUTPUT ;
    USE SIGNAL ;
    PORT
      LAYER met3 ;
        RECT 688.015 250.280 688.615 250.880 ;
    END
  END la_data_out[17]
  PIN la_data_out[18]
    DIRECTION OUTPUT ;
    USE SIGNAL ;
    PORT
      LAYER met3 ;
        RECT 688.015 251.640 688.615 252.240 ;
    END
  END la_data_out[18]
  PIN la_data_out[19]
    DIRECTION OUTPUT ;
    USE SIGNAL ;
    PORT
      LAYER met3 ;
        RECT 688.015 253.000 688.615 253.600 ;
    END
  END la_data_out[19]
  PIN la_data_out[1]
    DIRECTION OUTPUT ;
    USE SIGNAL ;
    PORT
      LAYER met3 ;
        RECT 688.015 228.520 688.615 229.120 ;
    END
  END la_data_out[1]
  PIN la_data_out[20]
    DIRECTION OUTPUT ;
    USE SIGNAL ;
    PORT
      LAYER met3 ;
        RECT 688.015 254.360 688.615 254.960 ;
    END
  END la_data_out[20]
  PIN la_data_out[21]
    DIRECTION OUTPUT ;
    USE SIGNAL ;
    PORT
      LAYER met3 ;
        RECT 688.015 255.720 688.615 256.320 ;
    END
  END la_data_out[21]
  PIN la_data_out[22]
    DIRECTION OUTPUT ;
    USE SIGNAL ;
    PORT
      LAYER met3 ;
        RECT 688.015 257.080 688.615 257.680 ;
    END
  END la_data_out[22]
  PIN la_data_out[23]
    DIRECTION OUTPUT ;
    USE SIGNAL ;
    PORT
      LAYER met3 ;
        RECT 688.015 258.440 688.615 259.040 ;
    END
  END la_data_out[23]
  PIN la_data_out[24]
    DIRECTION OUTPUT ;
    USE SIGNAL ;
    PORT
      LAYER met3 ;
        RECT 688.015 259.800 688.615 260.400 ;
    END
  END la_data_out[24]
  PIN la_data_out[25]
    DIRECTION OUTPUT ;
    USE SIGNAL ;
    PORT
      LAYER met3 ;
        RECT 688.015 261.160 688.615 261.760 ;
    END
  END la_data_out[25]
  PIN la_data_out[26]
    DIRECTION OUTPUT ;
    USE SIGNAL ;
    PORT
      LAYER met3 ;
        RECT 688.015 262.520 688.615 263.120 ;
    END
  END la_data_out[26]
  PIN la_data_out[27]
    DIRECTION OUTPUT ;
    USE SIGNAL ;
    PORT
      LAYER met3 ;
        RECT 688.015 263.880 688.615 264.480 ;
    END
  END la_data_out[27]
  PIN la_data_out[28]
    DIRECTION OUTPUT ;
    USE SIGNAL ;
    PORT
      LAYER met3 ;
        RECT 688.015 265.240 688.615 265.840 ;
    END
  END la_data_out[28]
  PIN la_data_out[29]
    DIRECTION OUTPUT ;
    USE SIGNAL ;
    PORT
      LAYER met3 ;
        RECT 688.015 266.600 688.615 267.200 ;
    END
  END la_data_out[29]
  PIN la_data_out[2]
    DIRECTION OUTPUT ;
    USE SIGNAL ;
    PORT
      LAYER met3 ;
        RECT 688.015 229.880 688.615 230.480 ;
    END
  END la_data_out[2]
  PIN la_data_out[30]
    DIRECTION OUTPUT ;
    USE SIGNAL ;
    PORT
      LAYER met3 ;
        RECT 688.015 267.960 688.615 268.560 ;
    END
  END la_data_out[30]
  PIN la_data_out[31]
    DIRECTION OUTPUT ;
    USE SIGNAL ;
    PORT
      LAYER met3 ;
        RECT 688.015 269.320 688.615 269.920 ;
    END
  END la_data_out[31]
  PIN la_data_out[32]
    DIRECTION OUTPUT ;
    USE SIGNAL ;
    PORT
      LAYER met3 ;
        RECT 688.015 270.680 688.615 271.280 ;
    END
  END la_data_out[32]
  PIN la_data_out[33]
    DIRECTION OUTPUT ;
    USE SIGNAL ;
    PORT
      LAYER met3 ;
        RECT 688.015 272.040 688.615 272.640 ;
    END
  END la_data_out[33]
  PIN la_data_out[34]
    DIRECTION OUTPUT ;
    USE SIGNAL ;
    PORT
      LAYER met3 ;
        RECT 688.015 273.400 688.615 274.000 ;
    END
  END la_data_out[34]
  PIN la_data_out[35]
    DIRECTION OUTPUT ;
    USE SIGNAL ;
    PORT
      LAYER met3 ;
        RECT 688.015 274.760 688.615 275.360 ;
    END
  END la_data_out[35]
  PIN la_data_out[36]
    DIRECTION OUTPUT ;
    USE SIGNAL ;
    PORT
      LAYER met3 ;
        RECT 688.015 276.120 688.615 276.720 ;
    END
  END la_data_out[36]
  PIN la_data_out[37]
    DIRECTION OUTPUT ;
    USE SIGNAL ;
    PORT
      LAYER met3 ;
        RECT 688.015 277.480 688.615 278.080 ;
    END
  END la_data_out[37]
  PIN la_data_out[38]
    DIRECTION OUTPUT ;
    USE SIGNAL ;
    PORT
      LAYER met3 ;
        RECT 688.015 278.840 688.615 279.440 ;
    END
  END la_data_out[38]
  PIN la_data_out[39]
    DIRECTION OUTPUT ;
    USE SIGNAL ;
    PORT
      LAYER met3 ;
        RECT 688.015 280.200 688.615 280.800 ;
    END
  END la_data_out[39]
  PIN la_data_out[3]
    DIRECTION OUTPUT ;
    USE SIGNAL ;
    PORT
      LAYER met3 ;
        RECT 688.015 231.240 688.615 231.840 ;
    END
  END la_data_out[3]
  PIN la_data_out[40]
    DIRECTION OUTPUT ;
    USE SIGNAL ;
    PORT
      LAYER met3 ;
        RECT 688.015 281.560 688.615 282.160 ;
    END
  END la_data_out[40]
  PIN la_data_out[41]
    DIRECTION OUTPUT ;
    USE SIGNAL ;
    PORT
      LAYER met3 ;
        RECT 688.015 282.920 688.615 283.520 ;
    END
  END la_data_out[41]
  PIN la_data_out[42]
    DIRECTION OUTPUT ;
    USE SIGNAL ;
    PORT
      LAYER met3 ;
        RECT 688.015 284.280 688.615 284.880 ;
    END
  END la_data_out[42]
  PIN la_data_out[43]
    DIRECTION OUTPUT ;
    USE SIGNAL ;
    PORT
      LAYER met3 ;
        RECT 688.015 285.640 688.615 286.240 ;
    END
  END la_data_out[43]
  PIN la_data_out[44]
    DIRECTION OUTPUT ;
    USE SIGNAL ;
    PORT
      LAYER met3 ;
        RECT 688.015 287.000 688.615 287.600 ;
    END
  END la_data_out[44]
  PIN la_data_out[45]
    DIRECTION OUTPUT ;
    USE SIGNAL ;
    PORT
      LAYER met3 ;
        RECT 688.015 288.360 688.615 288.960 ;
    END
  END la_data_out[45]
  PIN la_data_out[46]
    DIRECTION OUTPUT ;
    USE SIGNAL ;
    PORT
      LAYER met3 ;
        RECT 688.015 289.720 688.615 290.320 ;
    END
  END la_data_out[46]
  PIN la_data_out[47]
    DIRECTION OUTPUT ;
    USE SIGNAL ;
    PORT
      LAYER met3 ;
        RECT 688.015 291.080 688.615 291.680 ;
    END
  END la_data_out[47]
  PIN la_data_out[48]
    DIRECTION OUTPUT ;
    USE SIGNAL ;
    PORT
      LAYER met3 ;
        RECT 688.015 292.440 688.615 293.040 ;
    END
  END la_data_out[48]
  PIN la_data_out[49]
    DIRECTION OUTPUT ;
    USE SIGNAL ;
    PORT
      LAYER met3 ;
        RECT 688.015 293.800 688.615 294.400 ;
    END
  END la_data_out[49]
  PIN la_data_out[4]
    DIRECTION OUTPUT ;
    USE SIGNAL ;
    PORT
      LAYER met3 ;
        RECT 688.015 232.600 688.615 233.200 ;
    END
  END la_data_out[4]
  PIN la_data_out[50]
    DIRECTION OUTPUT ;
    USE SIGNAL ;
    PORT
      LAYER met3 ;
        RECT 688.015 295.160 688.615 295.760 ;
    END
  END la_data_out[50]
  PIN la_data_out[51]
    DIRECTION OUTPUT ;
    USE SIGNAL ;
    PORT
      LAYER met3 ;
        RECT 688.015 296.520 688.615 297.120 ;
    END
  END la_data_out[51]
  PIN la_data_out[52]
    DIRECTION OUTPUT ;
    USE SIGNAL ;
    PORT
      LAYER met3 ;
        RECT 688.015 297.880 688.615 298.480 ;
    END
  END la_data_out[52]
  PIN la_data_out[53]
    DIRECTION OUTPUT ;
    USE SIGNAL ;
    PORT
      LAYER met3 ;
        RECT 688.015 299.240 688.615 299.840 ;
    END
  END la_data_out[53]
  PIN la_data_out[54]
    DIRECTION OUTPUT ;
    USE SIGNAL ;
    PORT
      LAYER met3 ;
        RECT 688.015 300.600 688.615 301.200 ;
    END
  END la_data_out[54]
  PIN la_data_out[55]
    DIRECTION OUTPUT ;
    USE SIGNAL ;
    PORT
      LAYER met3 ;
        RECT 688.015 301.960 688.615 302.560 ;
    END
  END la_data_out[55]
  PIN la_data_out[56]
    DIRECTION OUTPUT ;
    USE SIGNAL ;
    PORT
      LAYER met3 ;
        RECT 688.015 303.320 688.615 303.920 ;
    END
  END la_data_out[56]
  PIN la_data_out[57]
    DIRECTION OUTPUT ;
    USE SIGNAL ;
    PORT
      LAYER met3 ;
        RECT 688.015 304.680 688.615 305.280 ;
    END
  END la_data_out[57]
  PIN la_data_out[58]
    DIRECTION OUTPUT ;
    USE SIGNAL ;
    PORT
      LAYER met3 ;
        RECT 688.015 306.040 688.615 306.640 ;
    END
  END la_data_out[58]
  PIN la_data_out[59]
    DIRECTION OUTPUT ;
    USE SIGNAL ;
    PORT
      LAYER met3 ;
        RECT 688.015 307.400 688.615 308.000 ;
    END
  END la_data_out[59]
  PIN la_data_out[5]
    DIRECTION OUTPUT ;
    USE SIGNAL ;
    PORT
      LAYER met3 ;
        RECT 688.015 233.960 688.615 234.560 ;
    END
  END la_data_out[5]
  PIN la_data_out[60]
    DIRECTION OUTPUT ;
    USE SIGNAL ;
    PORT
      LAYER met3 ;
        RECT 688.015 308.760 688.615 309.360 ;
    END
  END la_data_out[60]
  PIN la_data_out[61]
    DIRECTION OUTPUT ;
    USE SIGNAL ;
    PORT
      LAYER met3 ;
        RECT 688.015 310.120 688.615 310.720 ;
    END
  END la_data_out[61]
  PIN la_data_out[62]
    DIRECTION OUTPUT ;
    USE SIGNAL ;
    PORT
      LAYER met3 ;
        RECT 688.015 311.480 688.615 312.080 ;
    END
  END la_data_out[62]
  PIN la_data_out[63]
    DIRECTION OUTPUT ;
    USE SIGNAL ;
    PORT
      LAYER met3 ;
        RECT 688.015 312.840 688.615 313.440 ;
    END
  END la_data_out[63]
  PIN la_data_out[64]
    DIRECTION OUTPUT ;
    USE SIGNAL ;
    PORT
      LAYER met3 ;
        RECT 688.015 314.200 688.615 314.800 ;
    END
  END la_data_out[64]
  PIN la_data_out[65]
    DIRECTION OUTPUT ;
    USE SIGNAL ;
    PORT
      LAYER met3 ;
        RECT 688.015 315.560 688.615 316.160 ;
    END
  END la_data_out[65]
  PIN la_data_out[66]
    DIRECTION OUTPUT ;
    USE SIGNAL ;
    PORT
      LAYER met3 ;
        RECT 688.015 316.920 688.615 317.520 ;
    END
  END la_data_out[66]
  PIN la_data_out[67]
    DIRECTION OUTPUT ;
    USE SIGNAL ;
    PORT
      LAYER met3 ;
        RECT 688.015 318.280 688.615 318.880 ;
    END
  END la_data_out[67]
  PIN la_data_out[68]
    DIRECTION OUTPUT ;
    USE SIGNAL ;
    PORT
      LAYER met3 ;
        RECT 688.015 319.640 688.615 320.240 ;
    END
  END la_data_out[68]
  PIN la_data_out[69]
    DIRECTION OUTPUT ;
    USE SIGNAL ;
    PORT
      LAYER met3 ;
        RECT 688.015 321.000 688.615 321.600 ;
    END
  END la_data_out[69]
  PIN la_data_out[6]
    DIRECTION OUTPUT ;
    USE SIGNAL ;
    PORT
      LAYER met3 ;
        RECT 688.015 235.320 688.615 235.920 ;
    END
  END la_data_out[6]
  PIN la_data_out[70]
    DIRECTION OUTPUT ;
    USE SIGNAL ;
    PORT
      LAYER met3 ;
        RECT 688.015 322.360 688.615 322.960 ;
    END
  END la_data_out[70]
  PIN la_data_out[71]
    DIRECTION OUTPUT ;
    USE SIGNAL ;
    PORT
      LAYER met3 ;
        RECT 688.015 323.720 688.615 324.320 ;
    END
  END la_data_out[71]
  PIN la_data_out[72]
    DIRECTION OUTPUT ;
    USE SIGNAL ;
    PORT
      LAYER met3 ;
        RECT 688.015 325.080 688.615 325.680 ;
    END
  END la_data_out[72]
  PIN la_data_out[73]
    DIRECTION OUTPUT ;
    USE SIGNAL ;
    PORT
      LAYER met3 ;
        RECT 688.015 326.440 688.615 327.040 ;
    END
  END la_data_out[73]
  PIN la_data_out[74]
    DIRECTION OUTPUT ;
    USE SIGNAL ;
    PORT
      LAYER met3 ;
        RECT 688.015 327.800 688.615 328.400 ;
    END
  END la_data_out[74]
  PIN la_data_out[75]
    DIRECTION OUTPUT ;
    USE SIGNAL ;
    PORT
      LAYER met3 ;
        RECT 688.015 329.160 688.615 329.760 ;
    END
  END la_data_out[75]
  PIN la_data_out[76]
    DIRECTION OUTPUT ;
    USE SIGNAL ;
    PORT
      LAYER met3 ;
        RECT 688.015 330.520 688.615 331.120 ;
    END
  END la_data_out[76]
  PIN la_data_out[77]
    DIRECTION OUTPUT ;
    USE SIGNAL ;
    PORT
      LAYER met3 ;
        RECT 688.015 331.880 688.615 332.480 ;
    END
  END la_data_out[77]
  PIN la_data_out[78]
    DIRECTION OUTPUT ;
    USE SIGNAL ;
    PORT
      LAYER met3 ;
        RECT 688.015 333.240 688.615 333.840 ;
    END
  END la_data_out[78]
  PIN la_data_out[79]
    DIRECTION OUTPUT ;
    USE SIGNAL ;
    PORT
      LAYER met3 ;
        RECT 688.015 334.600 688.615 335.200 ;
    END
  END la_data_out[79]
  PIN la_data_out[7]
    DIRECTION OUTPUT ;
    USE SIGNAL ;
    PORT
      LAYER met3 ;
        RECT 688.015 236.680 688.615 237.280 ;
    END
  END la_data_out[7]
  PIN la_data_out[80]
    DIRECTION OUTPUT ;
    USE SIGNAL ;
    PORT
      LAYER met3 ;
        RECT 688.015 335.960 688.615 336.560 ;
    END
  END la_data_out[80]
  PIN la_data_out[81]
    DIRECTION OUTPUT ;
    USE SIGNAL ;
    PORT
      LAYER met3 ;
        RECT 688.015 337.320 688.615 337.920 ;
    END
  END la_data_out[81]
  PIN la_data_out[82]
    DIRECTION OUTPUT ;
    USE SIGNAL ;
    PORT
      LAYER met3 ;
        RECT 688.015 338.680 688.615 339.280 ;
    END
  END la_data_out[82]
  PIN la_data_out[83]
    DIRECTION OUTPUT ;
    USE SIGNAL ;
    PORT
      LAYER met3 ;
        RECT 688.015 340.040 688.615 340.640 ;
    END
  END la_data_out[83]
  PIN la_data_out[84]
    DIRECTION OUTPUT ;
    USE SIGNAL ;
    PORT
      LAYER met3 ;
        RECT 688.015 341.400 688.615 342.000 ;
    END
  END la_data_out[84]
  PIN la_data_out[85]
    DIRECTION OUTPUT ;
    USE SIGNAL ;
    PORT
      LAYER met3 ;
        RECT 688.015 342.760 688.615 343.360 ;
    END
  END la_data_out[85]
  PIN la_data_out[86]
    DIRECTION OUTPUT ;
    USE SIGNAL ;
    PORT
      LAYER met3 ;
        RECT 688.015 344.120 688.615 344.720 ;
    END
  END la_data_out[86]
  PIN la_data_out[87]
    DIRECTION OUTPUT ;
    USE SIGNAL ;
    PORT
      LAYER met3 ;
        RECT 688.015 345.480 688.615 346.080 ;
    END
  END la_data_out[87]
  PIN la_data_out[88]
    DIRECTION OUTPUT ;
    USE SIGNAL ;
    PORT
      LAYER met3 ;
        RECT 688.015 346.840 688.615 347.440 ;
    END
  END la_data_out[88]
  PIN la_data_out[89]
    DIRECTION OUTPUT ;
    USE SIGNAL ;
    PORT
      LAYER met3 ;
        RECT 688.015 348.200 688.615 348.800 ;
    END
  END la_data_out[89]
  PIN la_data_out[8]
    DIRECTION OUTPUT ;
    USE SIGNAL ;
    PORT
      LAYER met3 ;
        RECT 688.015 238.040 688.615 238.640 ;
    END
  END la_data_out[8]
  PIN la_data_out[90]
    DIRECTION OUTPUT ;
    USE SIGNAL ;
    PORT
      LAYER met3 ;
        RECT 688.015 349.560 688.615 350.160 ;
    END
  END la_data_out[90]
  PIN la_data_out[91]
    DIRECTION OUTPUT ;
    USE SIGNAL ;
    PORT
      LAYER met3 ;
        RECT 688.015 350.920 688.615 351.520 ;
    END
  END la_data_out[91]
  PIN la_data_out[92]
    DIRECTION OUTPUT ;
    USE SIGNAL ;
    PORT
      LAYER met3 ;
        RECT 688.015 352.280 688.615 352.880 ;
    END
  END la_data_out[92]
  PIN la_data_out[93]
    DIRECTION OUTPUT ;
    USE SIGNAL ;
    PORT
      LAYER met3 ;
        RECT 688.015 353.640 688.615 354.240 ;
    END
  END la_data_out[93]
  PIN la_data_out[94]
    DIRECTION OUTPUT ;
    USE SIGNAL ;
    PORT
      LAYER met3 ;
        RECT 688.015 355.000 688.615 355.600 ;
    END
  END la_data_out[94]
  PIN la_data_out[95]
    DIRECTION OUTPUT ;
    USE SIGNAL ;
    PORT
      LAYER met3 ;
        RECT 688.015 356.360 688.615 356.960 ;
    END
  END la_data_out[95]
  PIN la_data_out[96]
    DIRECTION OUTPUT ;
    USE SIGNAL ;
    PORT
      LAYER met3 ;
        RECT 688.015 357.720 688.615 358.320 ;
    END
  END la_data_out[96]
  PIN la_data_out[97]
    DIRECTION OUTPUT ;
    USE SIGNAL ;
    PORT
      LAYER met3 ;
        RECT 688.015 359.080 688.615 359.680 ;
    END
  END la_data_out[97]
  PIN la_data_out[98]
    DIRECTION OUTPUT ;
    USE SIGNAL ;
    PORT
      LAYER met3 ;
        RECT 688.015 360.440 688.615 361.040 ;
    END
  END la_data_out[98]
  PIN la_data_out[99]
    DIRECTION OUTPUT ;
    USE SIGNAL ;
    PORT
      LAYER met3 ;
        RECT 688.015 361.800 688.615 362.400 ;
    END
  END la_data_out[99]
  PIN la_data_out[9]
    DIRECTION OUTPUT ;
    USE SIGNAL ;
    PORT
      LAYER met3 ;
        RECT 688.015 239.400 688.615 240.000 ;
    END
  END la_data_out[9]
  PIN la_oenb[0]
    DIRECTION INPUT ;
    USE SIGNAL ;
    PORT
      LAYER met3 ;
        RECT 688.015 401.240 688.615 401.840 ;
    END
  END la_oenb[0]
  PIN la_oenb[100]
    DIRECTION INPUT ;
    USE SIGNAL ;
    PORT
      LAYER met3 ;
        RECT 688.015 537.240 688.615 537.840 ;
    END
  END la_oenb[100]
  PIN la_oenb[101]
    DIRECTION INPUT ;
    USE SIGNAL ;
    PORT
      LAYER met3 ;
        RECT 688.015 538.600 688.615 539.200 ;
    END
  END la_oenb[101]
  PIN la_oenb[102]
    DIRECTION INPUT ;
    USE SIGNAL ;
    PORT
      LAYER met3 ;
        RECT 688.015 539.960 688.615 540.560 ;
    END
  END la_oenb[102]
  PIN la_oenb[103]
    DIRECTION INPUT ;
    USE SIGNAL ;
    PORT
      LAYER met3 ;
        RECT 688.015 541.320 688.615 541.920 ;
    END
  END la_oenb[103]
  PIN la_oenb[104]
    DIRECTION INPUT ;
    USE SIGNAL ;
    PORT
      LAYER met3 ;
        RECT 688.015 542.680 688.615 543.280 ;
    END
  END la_oenb[104]
  PIN la_oenb[105]
    DIRECTION INPUT ;
    USE SIGNAL ;
    PORT
      LAYER met3 ;
        RECT 688.015 544.040 688.615 544.640 ;
    END
  END la_oenb[105]
  PIN la_oenb[106]
    DIRECTION INPUT ;
    USE SIGNAL ;
    PORT
      LAYER met3 ;
        RECT 688.015 545.400 688.615 546.000 ;
    END
  END la_oenb[106]
  PIN la_oenb[107]
    DIRECTION INPUT ;
    USE SIGNAL ;
    PORT
      LAYER met3 ;
        RECT 688.015 546.760 688.615 547.360 ;
    END
  END la_oenb[107]
  PIN la_oenb[108]
    DIRECTION INPUT ;
    USE SIGNAL ;
    PORT
      LAYER met3 ;
        RECT 688.015 548.120 688.615 548.720 ;
    END
  END la_oenb[108]
  PIN la_oenb[109]
    DIRECTION INPUT ;
    USE SIGNAL ;
    PORT
      LAYER met3 ;
        RECT 688.015 549.480 688.615 550.080 ;
    END
  END la_oenb[109]
  PIN la_oenb[10]
    DIRECTION INPUT ;
    USE SIGNAL ;
    PORT
      LAYER met3 ;
        RECT 688.015 414.840 688.615 415.440 ;
    END
  END la_oenb[10]
  PIN la_oenb[110]
    DIRECTION INPUT ;
    USE SIGNAL ;
    PORT
      LAYER met3 ;
        RECT 688.015 550.840 688.615 551.440 ;
    END
  END la_oenb[110]
  PIN la_oenb[111]
    DIRECTION INPUT ;
    USE SIGNAL ;
    PORT
      LAYER met3 ;
        RECT 688.015 552.200 688.615 552.800 ;
    END
  END la_oenb[111]
  PIN la_oenb[112]
    DIRECTION INPUT ;
    USE SIGNAL ;
    PORT
      LAYER met3 ;
        RECT 688.015 553.560 688.615 554.160 ;
    END
  END la_oenb[112]
  PIN la_oenb[113]
    DIRECTION INPUT ;
    USE SIGNAL ;
    PORT
      LAYER met3 ;
        RECT 688.015 554.920 688.615 555.520 ;
    END
  END la_oenb[113]
  PIN la_oenb[114]
    DIRECTION INPUT ;
    USE SIGNAL ;
    PORT
      LAYER met3 ;
        RECT 688.015 556.280 688.615 556.880 ;
    END
  END la_oenb[114]
  PIN la_oenb[115]
    DIRECTION INPUT ;
    USE SIGNAL ;
    PORT
      LAYER met3 ;
        RECT 688.015 557.640 688.615 558.240 ;
    END
  END la_oenb[115]
  PIN la_oenb[116]
    DIRECTION INPUT ;
    USE SIGNAL ;
    PORT
      LAYER met3 ;
        RECT 688.015 559.000 688.615 559.600 ;
    END
  END la_oenb[116]
  PIN la_oenb[117]
    DIRECTION INPUT ;
    USE SIGNAL ;
    PORT
      LAYER met3 ;
        RECT 688.015 560.360 688.615 560.960 ;
    END
  END la_oenb[117]
  PIN la_oenb[118]
    DIRECTION INPUT ;
    USE SIGNAL ;
    PORT
      LAYER met3 ;
        RECT 688.015 561.720 688.615 562.320 ;
    END
  END la_oenb[118]
  PIN la_oenb[119]
    DIRECTION INPUT ;
    USE SIGNAL ;
    PORT
      LAYER met3 ;
        RECT 688.015 563.080 688.615 563.680 ;
    END
  END la_oenb[119]
  PIN la_oenb[11]
    DIRECTION INPUT ;
    USE SIGNAL ;
    PORT
      LAYER met3 ;
        RECT 688.015 416.200 688.615 416.800 ;
    END
  END la_oenb[11]
  PIN la_oenb[120]
    DIRECTION INPUT ;
    USE SIGNAL ;
    PORT
      LAYER met3 ;
        RECT 688.015 564.440 688.615 565.040 ;
    END
  END la_oenb[120]
  PIN la_oenb[121]
    DIRECTION INPUT ;
    USE SIGNAL ;
    PORT
      LAYER met3 ;
        RECT 688.015 565.800 688.615 566.400 ;
    END
  END la_oenb[121]
  PIN la_oenb[122]
    DIRECTION INPUT ;
    USE SIGNAL ;
    PORT
      LAYER met3 ;
        RECT 688.015 567.160 688.615 567.760 ;
    END
  END la_oenb[122]
  PIN la_oenb[123]
    DIRECTION INPUT ;
    USE SIGNAL ;
    PORT
      LAYER met3 ;
        RECT 688.015 568.520 688.615 569.120 ;
    END
  END la_oenb[123]
  PIN la_oenb[124]
    DIRECTION INPUT ;
    USE SIGNAL ;
    PORT
      LAYER met3 ;
        RECT 688.015 569.880 688.615 570.480 ;
    END
  END la_oenb[124]
  PIN la_oenb[125]
    DIRECTION INPUT ;
    USE SIGNAL ;
    PORT
      LAYER met3 ;
        RECT 688.015 571.240 688.615 571.840 ;
    END
  END la_oenb[125]
  PIN la_oenb[126]
    DIRECTION INPUT ;
    USE SIGNAL ;
    PORT
      LAYER met3 ;
        RECT 688.015 572.600 688.615 573.200 ;
    END
  END la_oenb[126]
  PIN la_oenb[127]
    DIRECTION INPUT ;
    USE SIGNAL ;
    PORT
      LAYER met3 ;
        RECT 688.015 573.960 688.615 574.560 ;
    END
  END la_oenb[127]
  PIN la_oenb[12]
    DIRECTION INPUT ;
    USE SIGNAL ;
    PORT
      LAYER met3 ;
        RECT 688.015 417.560 688.615 418.160 ;
    END
  END la_oenb[12]
  PIN la_oenb[13]
    DIRECTION INPUT ;
    USE SIGNAL ;
    PORT
      LAYER met3 ;
        RECT 688.015 418.920 688.615 419.520 ;
    END
  END la_oenb[13]
  PIN la_oenb[14]
    DIRECTION INPUT ;
    USE SIGNAL ;
    PORT
      LAYER met3 ;
        RECT 688.015 420.280 688.615 420.880 ;
    END
  END la_oenb[14]
  PIN la_oenb[15]
    DIRECTION INPUT ;
    USE SIGNAL ;
    PORT
      LAYER met3 ;
        RECT 688.015 421.640 688.615 422.240 ;
    END
  END la_oenb[15]
  PIN la_oenb[16]
    DIRECTION INPUT ;
    USE SIGNAL ;
    PORT
      LAYER met3 ;
        RECT 688.015 423.000 688.615 423.600 ;
    END
  END la_oenb[16]
  PIN la_oenb[17]
    DIRECTION INPUT ;
    USE SIGNAL ;
    PORT
      LAYER met3 ;
        RECT 688.015 424.360 688.615 424.960 ;
    END
  END la_oenb[17]
  PIN la_oenb[18]
    DIRECTION INPUT ;
    USE SIGNAL ;
    PORT
      LAYER met3 ;
        RECT 688.015 425.720 688.615 426.320 ;
    END
  END la_oenb[18]
  PIN la_oenb[19]
    DIRECTION INPUT ;
    USE SIGNAL ;
    PORT
      LAYER met3 ;
        RECT 688.015 427.080 688.615 427.680 ;
    END
  END la_oenb[19]
  PIN la_oenb[1]
    DIRECTION INPUT ;
    USE SIGNAL ;
    PORT
      LAYER met3 ;
        RECT 688.015 402.600 688.615 403.200 ;
    END
  END la_oenb[1]
  PIN la_oenb[20]
    DIRECTION INPUT ;
    USE SIGNAL ;
    PORT
      LAYER met3 ;
        RECT 688.015 428.440 688.615 429.040 ;
    END
  END la_oenb[20]
  PIN la_oenb[21]
    DIRECTION INPUT ;
    USE SIGNAL ;
    PORT
      LAYER met3 ;
        RECT 688.015 429.800 688.615 430.400 ;
    END
  END la_oenb[21]
  PIN la_oenb[22]
    DIRECTION INPUT ;
    USE SIGNAL ;
    PORT
      LAYER met3 ;
        RECT 688.015 431.160 688.615 431.760 ;
    END
  END la_oenb[22]
  PIN la_oenb[23]
    DIRECTION INPUT ;
    USE SIGNAL ;
    PORT
      LAYER met3 ;
        RECT 688.015 432.520 688.615 433.120 ;
    END
  END la_oenb[23]
  PIN la_oenb[24]
    DIRECTION INPUT ;
    USE SIGNAL ;
    PORT
      LAYER met3 ;
        RECT 688.015 433.880 688.615 434.480 ;
    END
  END la_oenb[24]
  PIN la_oenb[25]
    DIRECTION INPUT ;
    USE SIGNAL ;
    PORT
      LAYER met3 ;
        RECT 688.015 435.240 688.615 435.840 ;
    END
  END la_oenb[25]
  PIN la_oenb[26]
    DIRECTION INPUT ;
    USE SIGNAL ;
    PORT
      LAYER met3 ;
        RECT 688.015 436.600 688.615 437.200 ;
    END
  END la_oenb[26]
  PIN la_oenb[27]
    DIRECTION INPUT ;
    USE SIGNAL ;
    PORT
      LAYER met3 ;
        RECT 688.015 437.960 688.615 438.560 ;
    END
  END la_oenb[27]
  PIN la_oenb[28]
    DIRECTION INPUT ;
    USE SIGNAL ;
    PORT
      LAYER met3 ;
        RECT 688.015 439.320 688.615 439.920 ;
    END
  END la_oenb[28]
  PIN la_oenb[29]
    DIRECTION INPUT ;
    USE SIGNAL ;
    PORT
      LAYER met3 ;
        RECT 688.015 440.680 688.615 441.280 ;
    END
  END la_oenb[29]
  PIN la_oenb[2]
    DIRECTION INPUT ;
    USE SIGNAL ;
    PORT
      LAYER met3 ;
        RECT 688.015 403.960 688.615 404.560 ;
    END
  END la_oenb[2]
  PIN la_oenb[30]
    DIRECTION INPUT ;
    USE SIGNAL ;
    PORT
      LAYER met3 ;
        RECT 688.015 442.040 688.615 442.640 ;
    END
  END la_oenb[30]
  PIN la_oenb[31]
    DIRECTION INPUT ;
    USE SIGNAL ;
    PORT
      LAYER met3 ;
        RECT 688.015 443.400 688.615 444.000 ;
    END
  END la_oenb[31]
  PIN la_oenb[32]
    DIRECTION INPUT ;
    USE SIGNAL ;
    PORT
      LAYER met3 ;
        RECT 688.015 444.760 688.615 445.360 ;
    END
  END la_oenb[32]
  PIN la_oenb[33]
    DIRECTION INPUT ;
    USE SIGNAL ;
    PORT
      LAYER met3 ;
        RECT 688.015 446.120 688.615 446.720 ;
    END
  END la_oenb[33]
  PIN la_oenb[34]
    DIRECTION INPUT ;
    USE SIGNAL ;
    PORT
      LAYER met3 ;
        RECT 688.015 447.480 688.615 448.080 ;
    END
  END la_oenb[34]
  PIN la_oenb[35]
    DIRECTION INPUT ;
    USE SIGNAL ;
    PORT
      LAYER met3 ;
        RECT 688.015 448.840 688.615 449.440 ;
    END
  END la_oenb[35]
  PIN la_oenb[36]
    DIRECTION INPUT ;
    USE SIGNAL ;
    PORT
      LAYER met3 ;
        RECT 688.015 450.200 688.615 450.800 ;
    END
  END la_oenb[36]
  PIN la_oenb[37]
    DIRECTION INPUT ;
    USE SIGNAL ;
    PORT
      LAYER met3 ;
        RECT 688.015 451.560 688.615 452.160 ;
    END
  END la_oenb[37]
  PIN la_oenb[38]
    DIRECTION INPUT ;
    USE SIGNAL ;
    PORT
      LAYER met3 ;
        RECT 688.015 452.920 688.615 453.520 ;
    END
  END la_oenb[38]
  PIN la_oenb[39]
    DIRECTION INPUT ;
    USE SIGNAL ;
    PORT
      LAYER met3 ;
        RECT 688.015 454.280 688.615 454.880 ;
    END
  END la_oenb[39]
  PIN la_oenb[3]
    DIRECTION INPUT ;
    USE SIGNAL ;
    PORT
      LAYER met3 ;
        RECT 688.015 405.320 688.615 405.920 ;
    END
  END la_oenb[3]
  PIN la_oenb[40]
    DIRECTION INPUT ;
    USE SIGNAL ;
    PORT
      LAYER met3 ;
        RECT 688.015 455.640 688.615 456.240 ;
    END
  END la_oenb[40]
  PIN la_oenb[41]
    DIRECTION INPUT ;
    USE SIGNAL ;
    PORT
      LAYER met3 ;
        RECT 688.015 457.000 688.615 457.600 ;
    END
  END la_oenb[41]
  PIN la_oenb[42]
    DIRECTION INPUT ;
    USE SIGNAL ;
    PORT
      LAYER met3 ;
        RECT 688.015 458.360 688.615 458.960 ;
    END
  END la_oenb[42]
  PIN la_oenb[43]
    DIRECTION INPUT ;
    USE SIGNAL ;
    PORT
      LAYER met3 ;
        RECT 688.015 459.720 688.615 460.320 ;
    END
  END la_oenb[43]
  PIN la_oenb[44]
    DIRECTION INPUT ;
    USE SIGNAL ;
    PORT
      LAYER met3 ;
        RECT 688.015 461.080 688.615 461.680 ;
    END
  END la_oenb[44]
  PIN la_oenb[45]
    DIRECTION INPUT ;
    USE SIGNAL ;
    PORT
      LAYER met3 ;
        RECT 688.015 462.440 688.615 463.040 ;
    END
  END la_oenb[45]
  PIN la_oenb[46]
    DIRECTION INPUT ;
    USE SIGNAL ;
    PORT
      LAYER met3 ;
        RECT 688.015 463.800 688.615 464.400 ;
    END
  END la_oenb[46]
  PIN la_oenb[47]
    DIRECTION INPUT ;
    USE SIGNAL ;
    PORT
      LAYER met3 ;
        RECT 688.015 465.160 688.615 465.760 ;
    END
  END la_oenb[47]
  PIN la_oenb[48]
    DIRECTION INPUT ;
    USE SIGNAL ;
    PORT
      LAYER met3 ;
        RECT 688.015 466.520 688.615 467.120 ;
    END
  END la_oenb[48]
  PIN la_oenb[49]
    DIRECTION INPUT ;
    USE SIGNAL ;
    PORT
      LAYER met3 ;
        RECT 688.015 467.880 688.615 468.480 ;
    END
  END la_oenb[49]
  PIN la_oenb[4]
    DIRECTION INPUT ;
    USE SIGNAL ;
    PORT
      LAYER met3 ;
        RECT 688.015 406.680 688.615 407.280 ;
    END
  END la_oenb[4]
  PIN la_oenb[50]
    DIRECTION INPUT ;
    USE SIGNAL ;
    PORT
      LAYER met3 ;
        RECT 688.015 469.240 688.615 469.840 ;
    END
  END la_oenb[50]
  PIN la_oenb[51]
    DIRECTION INPUT ;
    USE SIGNAL ;
    PORT
      LAYER met3 ;
        RECT 688.015 470.600 688.615 471.200 ;
    END
  END la_oenb[51]
  PIN la_oenb[52]
    DIRECTION INPUT ;
    USE SIGNAL ;
    PORT
      LAYER met3 ;
        RECT 688.015 471.960 688.615 472.560 ;
    END
  END la_oenb[52]
  PIN la_oenb[53]
    DIRECTION INPUT ;
    USE SIGNAL ;
    PORT
      LAYER met3 ;
        RECT 688.015 473.320 688.615 473.920 ;
    END
  END la_oenb[53]
  PIN la_oenb[54]
    DIRECTION INPUT ;
    USE SIGNAL ;
    PORT
      LAYER met3 ;
        RECT 688.015 474.680 688.615 475.280 ;
    END
  END la_oenb[54]
  PIN la_oenb[55]
    DIRECTION INPUT ;
    USE SIGNAL ;
    PORT
      LAYER met3 ;
        RECT 688.015 476.040 688.615 476.640 ;
    END
  END la_oenb[55]
  PIN la_oenb[56]
    DIRECTION INPUT ;
    USE SIGNAL ;
    PORT
      LAYER met3 ;
        RECT 688.015 477.400 688.615 478.000 ;
    END
  END la_oenb[56]
  PIN la_oenb[57]
    DIRECTION INPUT ;
    USE SIGNAL ;
    PORT
      LAYER met3 ;
        RECT 688.015 478.760 688.615 479.360 ;
    END
  END la_oenb[57]
  PIN la_oenb[58]
    DIRECTION INPUT ;
    USE SIGNAL ;
    PORT
      LAYER met3 ;
        RECT 688.015 480.120 688.615 480.720 ;
    END
  END la_oenb[58]
  PIN la_oenb[59]
    DIRECTION INPUT ;
    USE SIGNAL ;
    PORT
      LAYER met3 ;
        RECT 688.015 481.480 688.615 482.080 ;
    END
  END la_oenb[59]
  PIN la_oenb[5]
    DIRECTION INPUT ;
    USE SIGNAL ;
    PORT
      LAYER met3 ;
        RECT 688.015 408.040 688.615 408.640 ;
    END
  END la_oenb[5]
  PIN la_oenb[60]
    DIRECTION INPUT ;
    USE SIGNAL ;
    PORT
      LAYER met3 ;
        RECT 688.015 482.840 688.615 483.440 ;
    END
  END la_oenb[60]
  PIN la_oenb[61]
    DIRECTION INPUT ;
    USE SIGNAL ;
    PORT
      LAYER met3 ;
        RECT 688.015 484.200 688.615 484.800 ;
    END
  END la_oenb[61]
  PIN la_oenb[62]
    DIRECTION INPUT ;
    USE SIGNAL ;
    PORT
      LAYER met3 ;
        RECT 688.015 485.560 688.615 486.160 ;
    END
  END la_oenb[62]
  PIN la_oenb[63]
    DIRECTION INPUT ;
    USE SIGNAL ;
    PORT
      LAYER met3 ;
        RECT 688.015 486.920 688.615 487.520 ;
    END
  END la_oenb[63]
  PIN la_oenb[64]
    DIRECTION INPUT ;
    USE SIGNAL ;
    ANTENNAGATEAREA 0.647700 ;
    ANTENNADIFFAREA 0.434700 ;
    PORT
      LAYER met3 ;
        RECT 688.015 488.280 688.615 488.880 ;
    END
  END la_oenb[64]
  PIN la_oenb[65]
    DIRECTION INPUT ;
    USE SIGNAL ;
    ANTENNAGATEAREA 0.647700 ;
    ANTENNADIFFAREA 0.434700 ;
    PORT
      LAYER met3 ;
        RECT 688.015 489.640 688.615 490.240 ;
    END
  END la_oenb[65]
  PIN la_oenb[66]
    DIRECTION INPUT ;
    USE SIGNAL ;
    PORT
      LAYER met3 ;
        RECT 688.015 491.000 688.615 491.600 ;
    END
  END la_oenb[66]
  PIN la_oenb[67]
    DIRECTION INPUT ;
    USE SIGNAL ;
    PORT
      LAYER met3 ;
        RECT 688.015 492.360 688.615 492.960 ;
    END
  END la_oenb[67]
  PIN la_oenb[68]
    DIRECTION INPUT ;
    USE SIGNAL ;
    PORT
      LAYER met3 ;
        RECT 688.015 493.720 688.615 494.320 ;
    END
  END la_oenb[68]
  PIN la_oenb[69]
    DIRECTION INPUT ;
    USE SIGNAL ;
    PORT
      LAYER met3 ;
        RECT 688.015 495.080 688.615 495.680 ;
    END
  END la_oenb[69]
  PIN la_oenb[6]
    DIRECTION INPUT ;
    USE SIGNAL ;
    PORT
      LAYER met3 ;
        RECT 688.015 409.400 688.615 410.000 ;
    END
  END la_oenb[6]
  PIN la_oenb[70]
    DIRECTION INPUT ;
    USE SIGNAL ;
    PORT
      LAYER met3 ;
        RECT 688.015 496.440 688.615 497.040 ;
    END
  END la_oenb[70]
  PIN la_oenb[71]
    DIRECTION INPUT ;
    USE SIGNAL ;
    PORT
      LAYER met3 ;
        RECT 688.015 497.800 688.615 498.400 ;
    END
  END la_oenb[71]
  PIN la_oenb[72]
    DIRECTION INPUT ;
    USE SIGNAL ;
    PORT
      LAYER met3 ;
        RECT 688.015 499.160 688.615 499.760 ;
    END
  END la_oenb[72]
  PIN la_oenb[73]
    DIRECTION INPUT ;
    USE SIGNAL ;
    PORT
      LAYER met3 ;
        RECT 688.015 500.520 688.615 501.120 ;
    END
  END la_oenb[73]
  PIN la_oenb[74]
    DIRECTION INPUT ;
    USE SIGNAL ;
    PORT
      LAYER met3 ;
        RECT 688.015 501.880 688.615 502.480 ;
    END
  END la_oenb[74]
  PIN la_oenb[75]
    DIRECTION INPUT ;
    USE SIGNAL ;
    PORT
      LAYER met3 ;
        RECT 688.015 503.240 688.615 503.840 ;
    END
  END la_oenb[75]
  PIN la_oenb[76]
    DIRECTION INPUT ;
    USE SIGNAL ;
    PORT
      LAYER met3 ;
        RECT 688.015 504.600 688.615 505.200 ;
    END
  END la_oenb[76]
  PIN la_oenb[77]
    DIRECTION INPUT ;
    USE SIGNAL ;
    PORT
      LAYER met3 ;
        RECT 688.015 505.960 688.615 506.560 ;
    END
  END la_oenb[77]
  PIN la_oenb[78]
    DIRECTION INPUT ;
    USE SIGNAL ;
    PORT
      LAYER met3 ;
        RECT 688.015 507.320 688.615 507.920 ;
    END
  END la_oenb[78]
  PIN la_oenb[79]
    DIRECTION INPUT ;
    USE SIGNAL ;
    PORT
      LAYER met3 ;
        RECT 688.015 508.680 688.615 509.280 ;
    END
  END la_oenb[79]
  PIN la_oenb[7]
    DIRECTION INPUT ;
    USE SIGNAL ;
    PORT
      LAYER met3 ;
        RECT 688.015 410.760 688.615 411.360 ;
    END
  END la_oenb[7]
  PIN la_oenb[80]
    DIRECTION INPUT ;
    USE SIGNAL ;
    PORT
      LAYER met3 ;
        RECT 688.015 510.040 688.615 510.640 ;
    END
  END la_oenb[80]
  PIN la_oenb[81]
    DIRECTION INPUT ;
    USE SIGNAL ;
    PORT
      LAYER met3 ;
        RECT 688.015 511.400 688.615 512.000 ;
    END
  END la_oenb[81]
  PIN la_oenb[82]
    DIRECTION INPUT ;
    USE SIGNAL ;
    PORT
      LAYER met3 ;
        RECT 688.015 512.760 688.615 513.360 ;
    END
  END la_oenb[82]
  PIN la_oenb[83]
    DIRECTION INPUT ;
    USE SIGNAL ;
    PORT
      LAYER met3 ;
        RECT 688.015 514.120 688.615 514.720 ;
    END
  END la_oenb[83]
  PIN la_oenb[84]
    DIRECTION INPUT ;
    USE SIGNAL ;
    PORT
      LAYER met3 ;
        RECT 688.015 515.480 688.615 516.080 ;
    END
  END la_oenb[84]
  PIN la_oenb[85]
    DIRECTION INPUT ;
    USE SIGNAL ;
    PORT
      LAYER met3 ;
        RECT 688.015 516.840 688.615 517.440 ;
    END
  END la_oenb[85]
  PIN la_oenb[86]
    DIRECTION INPUT ;
    USE SIGNAL ;
    PORT
      LAYER met3 ;
        RECT 688.015 518.200 688.615 518.800 ;
    END
  END la_oenb[86]
  PIN la_oenb[87]
    DIRECTION INPUT ;
    USE SIGNAL ;
    PORT
      LAYER met3 ;
        RECT 688.015 519.560 688.615 520.160 ;
    END
  END la_oenb[87]
  PIN la_oenb[88]
    DIRECTION INPUT ;
    USE SIGNAL ;
    PORT
      LAYER met3 ;
        RECT 688.015 520.920 688.615 521.520 ;
    END
  END la_oenb[88]
  PIN la_oenb[89]
    DIRECTION INPUT ;
    USE SIGNAL ;
    PORT
      LAYER met3 ;
        RECT 688.015 522.280 688.615 522.880 ;
    END
  END la_oenb[89]
  PIN la_oenb[8]
    DIRECTION INPUT ;
    USE SIGNAL ;
    PORT
      LAYER met3 ;
        RECT 688.015 412.120 688.615 412.720 ;
    END
  END la_oenb[8]
  PIN la_oenb[90]
    DIRECTION INPUT ;
    USE SIGNAL ;
    PORT
      LAYER met3 ;
        RECT 688.015 523.640 688.615 524.240 ;
    END
  END la_oenb[90]
  PIN la_oenb[91]
    DIRECTION INPUT ;
    USE SIGNAL ;
    PORT
      LAYER met3 ;
        RECT 688.015 525.000 688.615 525.600 ;
    END
  END la_oenb[91]
  PIN la_oenb[92]
    DIRECTION INPUT ;
    USE SIGNAL ;
    PORT
      LAYER met3 ;
        RECT 688.015 526.360 688.615 526.960 ;
    END
  END la_oenb[92]
  PIN la_oenb[93]
    DIRECTION INPUT ;
    USE SIGNAL ;
    PORT
      LAYER met3 ;
        RECT 688.015 527.720 688.615 528.320 ;
    END
  END la_oenb[93]
  PIN la_oenb[94]
    DIRECTION INPUT ;
    USE SIGNAL ;
    PORT
      LAYER met3 ;
        RECT 688.015 529.080 688.615 529.680 ;
    END
  END la_oenb[94]
  PIN la_oenb[95]
    DIRECTION INPUT ;
    USE SIGNAL ;
    PORT
      LAYER met3 ;
        RECT 688.015 530.440 688.615 531.040 ;
    END
  END la_oenb[95]
  PIN la_oenb[96]
    DIRECTION INPUT ;
    USE SIGNAL ;
    PORT
      LAYER met3 ;
        RECT 688.015 531.800 688.615 532.400 ;
    END
  END la_oenb[96]
  PIN la_oenb[97]
    DIRECTION INPUT ;
    USE SIGNAL ;
    PORT
      LAYER met3 ;
        RECT 688.015 533.160 688.615 533.760 ;
    END
  END la_oenb[97]
  PIN la_oenb[98]
    DIRECTION INPUT ;
    USE SIGNAL ;
    PORT
      LAYER met3 ;
        RECT 688.015 534.520 688.615 535.120 ;
    END
  END la_oenb[98]
  PIN la_oenb[99]
    DIRECTION INPUT ;
    USE SIGNAL ;
    PORT
      LAYER met3 ;
        RECT 688.015 535.880 688.615 536.480 ;
    END
  END la_oenb[99]
  PIN la_oenb[9]
    DIRECTION INPUT ;
    USE SIGNAL ;
    PORT
      LAYER met3 ;
        RECT 688.015 413.480 688.615 414.080 ;
    END
  END la_oenb[9]
  PIN wb_clk_i
    DIRECTION INPUT ;
    USE SIGNAL ;
    ANTENNAGATEAREA 0.560700 ;
    ANTENNADIFFAREA 0.434700 ;
    PORT
      LAYER met2 ;
        RECT 6.070 0.000 6.350 0.280 ;
    END
  END wb_clk_i
  PIN wb_rst_i
    DIRECTION INPUT ;
    USE SIGNAL ;
    ANTENNAGATEAREA 0.593700 ;
    ANTENNADIFFAREA 0.434700 ;
    PORT
      LAYER met2 ;
        RECT 12.510 0.000 12.790 0.280 ;
    END
  END wb_rst_i
  PIN wbs_ack_o
    DIRECTION OUTPUT ;
    USE SIGNAL ;
    PORT
      LAYER met2 ;
        RECT 18.950 0.000 19.230 0.280 ;
    END
  END wbs_ack_o
  PIN wbs_adr_i[0]
    DIRECTION INPUT ;
    USE SIGNAL ;
    PORT
      LAYER met2 ;
        RECT 25.390 0.000 25.670 0.280 ;
    END
  END wbs_adr_i[0]
  PIN wbs_adr_i[10]
    DIRECTION INPUT ;
    USE SIGNAL ;
    PORT
      LAYER met2 ;
        RECT 89.790 0.000 90.070 0.280 ;
    END
  END wbs_adr_i[10]
  PIN wbs_adr_i[11]
    DIRECTION INPUT ;
    USE SIGNAL ;
    PORT
      LAYER met2 ;
        RECT 96.230 0.000 96.510 0.280 ;
    END
  END wbs_adr_i[11]
  PIN wbs_adr_i[12]
    DIRECTION INPUT ;
    USE SIGNAL ;
    PORT
      LAYER met2 ;
        RECT 102.670 0.000 102.950 0.280 ;
    END
  END wbs_adr_i[12]
  PIN wbs_adr_i[13]
    DIRECTION INPUT ;
    USE SIGNAL ;
    PORT
      LAYER met2 ;
        RECT 109.110 0.000 109.390 0.280 ;
    END
  END wbs_adr_i[13]
  PIN wbs_adr_i[14]
    DIRECTION INPUT ;
    USE SIGNAL ;
    PORT
      LAYER met2 ;
        RECT 115.550 0.000 115.830 0.280 ;
    END
  END wbs_adr_i[14]
  PIN wbs_adr_i[15]
    DIRECTION INPUT ;
    USE SIGNAL ;
    PORT
      LAYER met2 ;
        RECT 121.990 0.000 122.270 0.280 ;
    END
  END wbs_adr_i[15]
  PIN wbs_adr_i[16]
    DIRECTION INPUT ;
    USE SIGNAL ;
    PORT
      LAYER met2 ;
        RECT 128.430 0.000 128.710 0.280 ;
    END
  END wbs_adr_i[16]
  PIN wbs_adr_i[17]
    DIRECTION INPUT ;
    USE SIGNAL ;
    PORT
      LAYER met2 ;
        RECT 134.870 0.000 135.150 0.280 ;
    END
  END wbs_adr_i[17]
  PIN wbs_adr_i[18]
    DIRECTION INPUT ;
    USE SIGNAL ;
    PORT
      LAYER met2 ;
        RECT 141.310 0.000 141.590 0.280 ;
    END
  END wbs_adr_i[18]
  PIN wbs_adr_i[19]
    DIRECTION INPUT ;
    USE SIGNAL ;
    PORT
      LAYER met2 ;
        RECT 147.750 0.000 148.030 0.280 ;
    END
  END wbs_adr_i[19]
  PIN wbs_adr_i[1]
    DIRECTION INPUT ;
    USE SIGNAL ;
    PORT
      LAYER met2 ;
        RECT 31.830 0.000 32.110 0.280 ;
    END
  END wbs_adr_i[1]
  PIN wbs_adr_i[20]
    DIRECTION INPUT ;
    USE SIGNAL ;
    PORT
      LAYER met2 ;
        RECT 154.190 0.000 154.470 0.280 ;
    END
  END wbs_adr_i[20]
  PIN wbs_adr_i[21]
    DIRECTION INPUT ;
    USE SIGNAL ;
    PORT
      LAYER met2 ;
        RECT 160.630 0.000 160.910 0.280 ;
    END
  END wbs_adr_i[21]
  PIN wbs_adr_i[22]
    DIRECTION INPUT ;
    USE SIGNAL ;
    PORT
      LAYER met2 ;
        RECT 167.070 0.000 167.350 0.280 ;
    END
  END wbs_adr_i[22]
  PIN wbs_adr_i[23]
    DIRECTION INPUT ;
    USE SIGNAL ;
    PORT
      LAYER met2 ;
        RECT 173.510 0.000 173.790 0.280 ;
    END
  END wbs_adr_i[23]
  PIN wbs_adr_i[24]
    DIRECTION INPUT ;
    USE SIGNAL ;
    PORT
      LAYER met2 ;
        RECT 179.950 0.000 180.230 0.280 ;
    END
  END wbs_adr_i[24]
  PIN wbs_adr_i[25]
    DIRECTION INPUT ;
    USE SIGNAL ;
    PORT
      LAYER met2 ;
        RECT 186.390 0.000 186.670 0.280 ;
    END
  END wbs_adr_i[25]
  PIN wbs_adr_i[26]
    DIRECTION INPUT ;
    USE SIGNAL ;
    PORT
      LAYER met2 ;
        RECT 192.830 0.000 193.110 0.280 ;
    END
  END wbs_adr_i[26]
  PIN wbs_adr_i[27]
    DIRECTION INPUT ;
    USE SIGNAL ;
    PORT
      LAYER met2 ;
        RECT 199.270 0.000 199.550 0.280 ;
    END
  END wbs_adr_i[27]
  PIN wbs_adr_i[28]
    DIRECTION INPUT ;
    USE SIGNAL ;
    PORT
      LAYER met2 ;
        RECT 205.710 0.000 205.990 0.280 ;
    END
  END wbs_adr_i[28]
  PIN wbs_adr_i[29]
    DIRECTION INPUT ;
    USE SIGNAL ;
    PORT
      LAYER met2 ;
        RECT 212.150 0.000 212.430 0.280 ;
    END
  END wbs_adr_i[29]
  PIN wbs_adr_i[2]
    DIRECTION INPUT ;
    USE SIGNAL ;
    PORT
      LAYER met2 ;
        RECT 38.270 0.000 38.550 0.280 ;
    END
  END wbs_adr_i[2]
  PIN wbs_adr_i[30]
    DIRECTION INPUT ;
    USE SIGNAL ;
    PORT
      LAYER met2 ;
        RECT 218.590 0.000 218.870 0.280 ;
    END
  END wbs_adr_i[30]
  PIN wbs_adr_i[31]
    DIRECTION INPUT ;
    USE SIGNAL ;
    PORT
      LAYER met2 ;
        RECT 225.030 0.000 225.310 0.280 ;
    END
  END wbs_adr_i[31]
  PIN wbs_adr_i[3]
    DIRECTION INPUT ;
    USE SIGNAL ;
    PORT
      LAYER met2 ;
        RECT 44.710 0.000 44.990 0.280 ;
    END
  END wbs_adr_i[3]
  PIN wbs_adr_i[4]
    DIRECTION INPUT ;
    USE SIGNAL ;
    PORT
      LAYER met2 ;
        RECT 51.150 0.000 51.430 0.280 ;
    END
  END wbs_adr_i[4]
  PIN wbs_adr_i[5]
    DIRECTION INPUT ;
    USE SIGNAL ;
    PORT
      LAYER met2 ;
        RECT 57.590 0.000 57.870 0.280 ;
    END
  END wbs_adr_i[5]
  PIN wbs_adr_i[6]
    DIRECTION INPUT ;
    USE SIGNAL ;
    PORT
      LAYER met2 ;
        RECT 64.030 0.000 64.310 0.280 ;
    END
  END wbs_adr_i[6]
  PIN wbs_adr_i[7]
    DIRECTION INPUT ;
    USE SIGNAL ;
    PORT
      LAYER met2 ;
        RECT 70.470 0.000 70.750 0.280 ;
    END
  END wbs_adr_i[7]
  PIN wbs_adr_i[8]
    DIRECTION INPUT ;
    USE SIGNAL ;
    PORT
      LAYER met2 ;
        RECT 76.910 0.000 77.190 0.280 ;
    END
  END wbs_adr_i[8]
  PIN wbs_adr_i[9]
    DIRECTION INPUT ;
    USE SIGNAL ;
    PORT
      LAYER met2 ;
        RECT 83.350 0.000 83.630 0.280 ;
    END
  END wbs_adr_i[9]
  PIN wbs_cyc_i
    DIRECTION INPUT ;
    USE SIGNAL ;
    PORT
      LAYER met2 ;
        RECT 231.470 0.000 231.750 0.280 ;
    END
  END wbs_cyc_i
  PIN wbs_dat_i[0]
    DIRECTION INPUT ;
    USE SIGNAL ;
    PORT
      LAYER met2 ;
        RECT 237.910 0.000 238.190 0.280 ;
    END
  END wbs_dat_i[0]
  PIN wbs_dat_i[10]
    DIRECTION INPUT ;
    USE SIGNAL ;
    PORT
      LAYER met2 ;
        RECT 302.310 0.000 302.590 0.280 ;
    END
  END wbs_dat_i[10]
  PIN wbs_dat_i[11]
    DIRECTION INPUT ;
    USE SIGNAL ;
    PORT
      LAYER met2 ;
        RECT 308.750 0.000 309.030 0.280 ;
    END
  END wbs_dat_i[11]
  PIN wbs_dat_i[12]
    DIRECTION INPUT ;
    USE SIGNAL ;
    PORT
      LAYER met2 ;
        RECT 315.190 0.000 315.470 0.280 ;
    END
  END wbs_dat_i[12]
  PIN wbs_dat_i[13]
    DIRECTION INPUT ;
    USE SIGNAL ;
    PORT
      LAYER met2 ;
        RECT 321.630 0.000 321.910 0.280 ;
    END
  END wbs_dat_i[13]
  PIN wbs_dat_i[14]
    DIRECTION INPUT ;
    USE SIGNAL ;
    PORT
      LAYER met2 ;
        RECT 328.070 0.000 328.350 0.280 ;
    END
  END wbs_dat_i[14]
  PIN wbs_dat_i[15]
    DIRECTION INPUT ;
    USE SIGNAL ;
    PORT
      LAYER met2 ;
        RECT 334.510 0.000 334.790 0.280 ;
    END
  END wbs_dat_i[15]
  PIN wbs_dat_i[16]
    DIRECTION INPUT ;
    USE SIGNAL ;
    PORT
      LAYER met2 ;
        RECT 340.950 0.000 341.230 0.280 ;
    END
  END wbs_dat_i[16]
  PIN wbs_dat_i[17]
    DIRECTION INPUT ;
    USE SIGNAL ;
    PORT
      LAYER met2 ;
        RECT 347.390 0.000 347.670 0.280 ;
    END
  END wbs_dat_i[17]
  PIN wbs_dat_i[18]
    DIRECTION INPUT ;
    USE SIGNAL ;
    PORT
      LAYER met2 ;
        RECT 353.830 0.000 354.110 0.280 ;
    END
  END wbs_dat_i[18]
  PIN wbs_dat_i[19]
    DIRECTION INPUT ;
    USE SIGNAL ;
    PORT
      LAYER met2 ;
        RECT 360.270 0.000 360.550 0.280 ;
    END
  END wbs_dat_i[19]
  PIN wbs_dat_i[1]
    DIRECTION INPUT ;
    USE SIGNAL ;
    PORT
      LAYER met2 ;
        RECT 244.350 0.000 244.630 0.280 ;
    END
  END wbs_dat_i[1]
  PIN wbs_dat_i[20]
    DIRECTION INPUT ;
    USE SIGNAL ;
    PORT
      LAYER met2 ;
        RECT 366.710 0.000 366.990 0.280 ;
    END
  END wbs_dat_i[20]
  PIN wbs_dat_i[21]
    DIRECTION INPUT ;
    USE SIGNAL ;
    PORT
      LAYER met2 ;
        RECT 373.150 0.000 373.430 0.280 ;
    END
  END wbs_dat_i[21]
  PIN wbs_dat_i[22]
    DIRECTION INPUT ;
    USE SIGNAL ;
    PORT
      LAYER met2 ;
        RECT 379.590 0.000 379.870 0.280 ;
    END
  END wbs_dat_i[22]
  PIN wbs_dat_i[23]
    DIRECTION INPUT ;
    USE SIGNAL ;
    PORT
      LAYER met2 ;
        RECT 386.030 0.000 386.310 0.280 ;
    END
  END wbs_dat_i[23]
  PIN wbs_dat_i[24]
    DIRECTION INPUT ;
    USE SIGNAL ;
    PORT
      LAYER met2 ;
        RECT 392.470 0.000 392.750 0.280 ;
    END
  END wbs_dat_i[24]
  PIN wbs_dat_i[25]
    DIRECTION INPUT ;
    USE SIGNAL ;
    PORT
      LAYER met2 ;
        RECT 398.910 0.000 399.190 0.280 ;
    END
  END wbs_dat_i[25]
  PIN wbs_dat_i[26]
    DIRECTION INPUT ;
    USE SIGNAL ;
    PORT
      LAYER met2 ;
        RECT 405.350 0.000 405.630 0.280 ;
    END
  END wbs_dat_i[26]
  PIN wbs_dat_i[27]
    DIRECTION INPUT ;
    USE SIGNAL ;
    PORT
      LAYER met2 ;
        RECT 411.790 0.000 412.070 0.280 ;
    END
  END wbs_dat_i[27]
  PIN wbs_dat_i[28]
    DIRECTION INPUT ;
    USE SIGNAL ;
    PORT
      LAYER met2 ;
        RECT 418.230 0.000 418.510 0.280 ;
    END
  END wbs_dat_i[28]
  PIN wbs_dat_i[29]
    DIRECTION INPUT ;
    USE SIGNAL ;
    PORT
      LAYER met2 ;
        RECT 424.670 0.000 424.950 0.280 ;
    END
  END wbs_dat_i[29]
  PIN wbs_dat_i[2]
    DIRECTION INPUT ;
    USE SIGNAL ;
    PORT
      LAYER met2 ;
        RECT 250.790 0.000 251.070 0.280 ;
    END
  END wbs_dat_i[2]
  PIN wbs_dat_i[30]
    DIRECTION INPUT ;
    USE SIGNAL ;
    PORT
      LAYER met2 ;
        RECT 431.110 0.000 431.390 0.280 ;
    END
  END wbs_dat_i[30]
  PIN wbs_dat_i[31]
    DIRECTION INPUT ;
    USE SIGNAL ;
    PORT
      LAYER met2 ;
        RECT 437.550 0.000 437.830 0.280 ;
    END
  END wbs_dat_i[31]
  PIN wbs_dat_i[3]
    DIRECTION INPUT ;
    USE SIGNAL ;
    PORT
      LAYER met2 ;
        RECT 257.230 0.000 257.510 0.280 ;
    END
  END wbs_dat_i[3]
  PIN wbs_dat_i[4]
    DIRECTION INPUT ;
    USE SIGNAL ;
    PORT
      LAYER met2 ;
        RECT 263.670 0.000 263.950 0.280 ;
    END
  END wbs_dat_i[4]
  PIN wbs_dat_i[5]
    DIRECTION INPUT ;
    USE SIGNAL ;
    PORT
      LAYER met2 ;
        RECT 270.110 0.000 270.390 0.280 ;
    END
  END wbs_dat_i[5]
  PIN wbs_dat_i[6]
    DIRECTION INPUT ;
    USE SIGNAL ;
    PORT
      LAYER met2 ;
        RECT 276.550 0.000 276.830 0.280 ;
    END
  END wbs_dat_i[6]
  PIN wbs_dat_i[7]
    DIRECTION INPUT ;
    USE SIGNAL ;
    PORT
      LAYER met2 ;
        RECT 282.990 0.000 283.270 0.280 ;
    END
  END wbs_dat_i[7]
  PIN wbs_dat_i[8]
    DIRECTION INPUT ;
    USE SIGNAL ;
    PORT
      LAYER met2 ;
        RECT 289.430 0.000 289.710 0.280 ;
    END
  END wbs_dat_i[8]
  PIN wbs_dat_i[9]
    DIRECTION INPUT ;
    USE SIGNAL ;
    PORT
      LAYER met2 ;
        RECT 295.870 0.000 296.150 0.280 ;
    END
  END wbs_dat_i[9]
  PIN wbs_dat_o[0]
    DIRECTION OUTPUT ;
    USE SIGNAL ;
    PORT
      LAYER met2 ;
        RECT 443.990 0.000 444.270 0.280 ;
    END
  END wbs_dat_o[0]
  PIN wbs_dat_o[10]
    DIRECTION OUTPUT ;
    USE SIGNAL ;
    PORT
      LAYER met2 ;
        RECT 508.390 0.000 508.670 0.280 ;
    END
  END wbs_dat_o[10]
  PIN wbs_dat_o[11]
    DIRECTION OUTPUT ;
    USE SIGNAL ;
    PORT
      LAYER met2 ;
        RECT 514.830 0.000 515.110 0.280 ;
    END
  END wbs_dat_o[11]
  PIN wbs_dat_o[12]
    DIRECTION OUTPUT ;
    USE SIGNAL ;
    PORT
      LAYER met2 ;
        RECT 521.270 0.000 521.550 0.280 ;
    END
  END wbs_dat_o[12]
  PIN wbs_dat_o[13]
    DIRECTION OUTPUT ;
    USE SIGNAL ;
    PORT
      LAYER met2 ;
        RECT 527.710 0.000 527.990 0.280 ;
    END
  END wbs_dat_o[13]
  PIN wbs_dat_o[14]
    DIRECTION OUTPUT ;
    USE SIGNAL ;
    PORT
      LAYER met2 ;
        RECT 534.150 0.000 534.430 0.280 ;
    END
  END wbs_dat_o[14]
  PIN wbs_dat_o[15]
    DIRECTION OUTPUT ;
    USE SIGNAL ;
    PORT
      LAYER met2 ;
        RECT 540.590 0.000 540.870 0.280 ;
    END
  END wbs_dat_o[15]
  PIN wbs_dat_o[16]
    DIRECTION OUTPUT ;
    USE SIGNAL ;
    PORT
      LAYER met2 ;
        RECT 547.030 0.000 547.310 0.280 ;
    END
  END wbs_dat_o[16]
  PIN wbs_dat_o[17]
    DIRECTION OUTPUT ;
    USE SIGNAL ;
    PORT
      LAYER met2 ;
        RECT 553.470 0.000 553.750 0.280 ;
    END
  END wbs_dat_o[17]
  PIN wbs_dat_o[18]
    DIRECTION OUTPUT ;
    USE SIGNAL ;
    PORT
      LAYER met2 ;
        RECT 559.910 0.000 560.190 0.280 ;
    END
  END wbs_dat_o[18]
  PIN wbs_dat_o[19]
    DIRECTION OUTPUT ;
    USE SIGNAL ;
    PORT
      LAYER met2 ;
        RECT 566.350 0.000 566.630 0.280 ;
    END
  END wbs_dat_o[19]
  PIN wbs_dat_o[1]
    DIRECTION OUTPUT ;
    USE SIGNAL ;
    PORT
      LAYER met2 ;
        RECT 450.430 0.000 450.710 0.280 ;
    END
  END wbs_dat_o[1]
  PIN wbs_dat_o[20]
    DIRECTION OUTPUT ;
    USE SIGNAL ;
    PORT
      LAYER met2 ;
        RECT 572.790 0.000 573.070 0.280 ;
    END
  END wbs_dat_o[20]
  PIN wbs_dat_o[21]
    DIRECTION OUTPUT ;
    USE SIGNAL ;
    PORT
      LAYER met2 ;
        RECT 579.230 0.000 579.510 0.280 ;
    END
  END wbs_dat_o[21]
  PIN wbs_dat_o[22]
    DIRECTION OUTPUT ;
    USE SIGNAL ;
    PORT
      LAYER met2 ;
        RECT 585.670 0.000 585.950 0.280 ;
    END
  END wbs_dat_o[22]
  PIN wbs_dat_o[23]
    DIRECTION OUTPUT ;
    USE SIGNAL ;
    PORT
      LAYER met2 ;
        RECT 592.110 0.000 592.390 0.280 ;
    END
  END wbs_dat_o[23]
  PIN wbs_dat_o[24]
    DIRECTION OUTPUT ;
    USE SIGNAL ;
    PORT
      LAYER met2 ;
        RECT 598.550 0.000 598.830 0.280 ;
    END
  END wbs_dat_o[24]
  PIN wbs_dat_o[25]
    DIRECTION OUTPUT ;
    USE SIGNAL ;
    PORT
      LAYER met2 ;
        RECT 604.990 0.000 605.270 0.280 ;
    END
  END wbs_dat_o[25]
  PIN wbs_dat_o[26]
    DIRECTION OUTPUT ;
    USE SIGNAL ;
    PORT
      LAYER met2 ;
        RECT 611.430 0.000 611.710 0.280 ;
    END
  END wbs_dat_o[26]
  PIN wbs_dat_o[27]
    DIRECTION OUTPUT ;
    USE SIGNAL ;
    PORT
      LAYER met2 ;
        RECT 617.870 0.000 618.150 0.280 ;
    END
  END wbs_dat_o[27]
  PIN wbs_dat_o[28]
    DIRECTION OUTPUT ;
    USE SIGNAL ;
    PORT
      LAYER met2 ;
        RECT 624.310 0.000 624.590 0.280 ;
    END
  END wbs_dat_o[28]
  PIN wbs_dat_o[29]
    DIRECTION OUTPUT ;
    USE SIGNAL ;
    PORT
      LAYER met2 ;
        RECT 630.750 0.000 631.030 0.280 ;
    END
  END wbs_dat_o[29]
  PIN wbs_dat_o[2]
    DIRECTION OUTPUT ;
    USE SIGNAL ;
    PORT
      LAYER met2 ;
        RECT 456.870 0.000 457.150 0.280 ;
    END
  END wbs_dat_o[2]
  PIN wbs_dat_o[30]
    DIRECTION OUTPUT ;
    USE SIGNAL ;
    PORT
      LAYER met2 ;
        RECT 637.190 0.000 637.470 0.280 ;
    END
  END wbs_dat_o[30]
  PIN wbs_dat_o[31]
    DIRECTION OUTPUT ;
    USE SIGNAL ;
    PORT
      LAYER met2 ;
        RECT 643.630 0.000 643.910 0.280 ;
    END
  END wbs_dat_o[31]
  PIN wbs_dat_o[3]
    DIRECTION OUTPUT ;
    USE SIGNAL ;
    PORT
      LAYER met2 ;
        RECT 463.310 0.000 463.590 0.280 ;
    END
  END wbs_dat_o[3]
  PIN wbs_dat_o[4]
    DIRECTION OUTPUT ;
    USE SIGNAL ;
    PORT
      LAYER met2 ;
        RECT 469.750 0.000 470.030 0.280 ;
    END
  END wbs_dat_o[4]
  PIN wbs_dat_o[5]
    DIRECTION OUTPUT ;
    USE SIGNAL ;
    PORT
      LAYER met2 ;
        RECT 476.190 0.000 476.470 0.280 ;
    END
  END wbs_dat_o[5]
  PIN wbs_dat_o[6]
    DIRECTION OUTPUT ;
    USE SIGNAL ;
    PORT
      LAYER met2 ;
        RECT 482.630 0.000 482.910 0.280 ;
    END
  END wbs_dat_o[6]
  PIN wbs_dat_o[7]
    DIRECTION OUTPUT ;
    USE SIGNAL ;
    PORT
      LAYER met2 ;
        RECT 489.070 0.000 489.350 0.280 ;
    END
  END wbs_dat_o[7]
  PIN wbs_dat_o[8]
    DIRECTION OUTPUT ;
    USE SIGNAL ;
    PORT
      LAYER met2 ;
        RECT 495.510 0.000 495.790 0.280 ;
    END
  END wbs_dat_o[8]
  PIN wbs_dat_o[9]
    DIRECTION OUTPUT ;
    USE SIGNAL ;
    PORT
      LAYER met2 ;
        RECT 501.950 0.000 502.230 0.280 ;
    END
  END wbs_dat_o[9]
  PIN wbs_sel_i[0]
    DIRECTION INPUT ;
    USE SIGNAL ;
    PORT
      LAYER met2 ;
        RECT 650.070 0.000 650.350 0.280 ;
    END
  END wbs_sel_i[0]
  PIN wbs_sel_i[1]
    DIRECTION INPUT ;
    USE SIGNAL ;
    PORT
      LAYER met2 ;
        RECT 656.510 0.000 656.790 0.280 ;
    END
  END wbs_sel_i[1]
  PIN wbs_sel_i[2]
    DIRECTION INPUT ;
    USE SIGNAL ;
    PORT
      LAYER met2 ;
        RECT 662.950 0.000 663.230 0.280 ;
    END
  END wbs_sel_i[2]
  PIN wbs_sel_i[3]
    DIRECTION INPUT ;
    USE SIGNAL ;
    PORT
      LAYER met2 ;
        RECT 669.390 0.000 669.670 0.280 ;
    END
  END wbs_sel_i[3]
  PIN wbs_stb_i
    DIRECTION INPUT ;
    USE SIGNAL ;
    PORT
      LAYER met2 ;
        RECT 675.830 0.000 676.110 0.280 ;
    END
  END wbs_stb_i
  PIN wbs_we_i
    DIRECTION INPUT ;
    USE SIGNAL ;
    PORT
      LAYER met2 ;
        RECT 682.270 0.000 682.550 0.280 ;
    END
  END wbs_we_i
  OBS
      LAYER nwell ;
        RECT 5.330 10.795 682.830 688.350 ;
      LAYER li1 ;
        RECT 5.520 10.795 682.640 688.245 ;
      LAYER met1 ;
        RECT 5.520 0.040 687.170 688.400 ;
      LAYER met2 ;
        RECT 6.140 0.560 687.150 688.345 ;
        RECT 6.630 0.010 12.230 0.560 ;
        RECT 13.070 0.010 18.670 0.560 ;
        RECT 19.510 0.010 25.110 0.560 ;
        RECT 25.950 0.010 31.550 0.560 ;
        RECT 32.390 0.010 37.990 0.560 ;
        RECT 38.830 0.010 44.430 0.560 ;
        RECT 45.270 0.010 50.870 0.560 ;
        RECT 51.710 0.010 57.310 0.560 ;
        RECT 58.150 0.010 63.750 0.560 ;
        RECT 64.590 0.010 70.190 0.560 ;
        RECT 71.030 0.010 76.630 0.560 ;
        RECT 77.470 0.010 83.070 0.560 ;
        RECT 83.910 0.010 89.510 0.560 ;
        RECT 90.350 0.010 95.950 0.560 ;
        RECT 96.790 0.010 102.390 0.560 ;
        RECT 103.230 0.010 108.830 0.560 ;
        RECT 109.670 0.010 115.270 0.560 ;
        RECT 116.110 0.010 121.710 0.560 ;
        RECT 122.550 0.010 128.150 0.560 ;
        RECT 128.990 0.010 134.590 0.560 ;
        RECT 135.430 0.010 141.030 0.560 ;
        RECT 141.870 0.010 147.470 0.560 ;
        RECT 148.310 0.010 153.910 0.560 ;
        RECT 154.750 0.010 160.350 0.560 ;
        RECT 161.190 0.010 166.790 0.560 ;
        RECT 167.630 0.010 173.230 0.560 ;
        RECT 174.070 0.010 179.670 0.560 ;
        RECT 180.510 0.010 186.110 0.560 ;
        RECT 186.950 0.010 192.550 0.560 ;
        RECT 193.390 0.010 198.990 0.560 ;
        RECT 199.830 0.010 205.430 0.560 ;
        RECT 206.270 0.010 211.870 0.560 ;
        RECT 212.710 0.010 218.310 0.560 ;
        RECT 219.150 0.010 224.750 0.560 ;
        RECT 225.590 0.010 231.190 0.560 ;
        RECT 232.030 0.010 237.630 0.560 ;
        RECT 238.470 0.010 244.070 0.560 ;
        RECT 244.910 0.010 250.510 0.560 ;
        RECT 251.350 0.010 256.950 0.560 ;
        RECT 257.790 0.010 263.390 0.560 ;
        RECT 264.230 0.010 269.830 0.560 ;
        RECT 270.670 0.010 276.270 0.560 ;
        RECT 277.110 0.010 282.710 0.560 ;
        RECT 283.550 0.010 289.150 0.560 ;
        RECT 289.990 0.010 295.590 0.560 ;
        RECT 296.430 0.010 302.030 0.560 ;
        RECT 302.870 0.010 308.470 0.560 ;
        RECT 309.310 0.010 314.910 0.560 ;
        RECT 315.750 0.010 321.350 0.560 ;
        RECT 322.190 0.010 327.790 0.560 ;
        RECT 328.630 0.010 334.230 0.560 ;
        RECT 335.070 0.010 340.670 0.560 ;
        RECT 341.510 0.010 347.110 0.560 ;
        RECT 347.950 0.010 353.550 0.560 ;
        RECT 354.390 0.010 359.990 0.560 ;
        RECT 360.830 0.010 366.430 0.560 ;
        RECT 367.270 0.010 372.870 0.560 ;
        RECT 373.710 0.010 379.310 0.560 ;
        RECT 380.150 0.010 385.750 0.560 ;
        RECT 386.590 0.010 392.190 0.560 ;
        RECT 393.030 0.010 398.630 0.560 ;
        RECT 399.470 0.010 405.070 0.560 ;
        RECT 405.910 0.010 411.510 0.560 ;
        RECT 412.350 0.010 417.950 0.560 ;
        RECT 418.790 0.010 424.390 0.560 ;
        RECT 425.230 0.010 430.830 0.560 ;
        RECT 431.670 0.010 437.270 0.560 ;
        RECT 438.110 0.010 443.710 0.560 ;
        RECT 444.550 0.010 450.150 0.560 ;
        RECT 450.990 0.010 456.590 0.560 ;
        RECT 457.430 0.010 463.030 0.560 ;
        RECT 463.870 0.010 469.470 0.560 ;
        RECT 470.310 0.010 475.910 0.560 ;
        RECT 476.750 0.010 482.350 0.560 ;
        RECT 483.190 0.010 488.790 0.560 ;
        RECT 489.630 0.010 495.230 0.560 ;
        RECT 496.070 0.010 501.670 0.560 ;
        RECT 502.510 0.010 508.110 0.560 ;
        RECT 508.950 0.010 514.550 0.560 ;
        RECT 515.390 0.010 520.990 0.560 ;
        RECT 521.830 0.010 527.430 0.560 ;
        RECT 528.270 0.010 533.870 0.560 ;
        RECT 534.710 0.010 540.310 0.560 ;
        RECT 541.150 0.010 546.750 0.560 ;
        RECT 547.590 0.010 553.190 0.560 ;
        RECT 554.030 0.010 559.630 0.560 ;
        RECT 560.470 0.010 566.070 0.560 ;
        RECT 566.910 0.010 572.510 0.560 ;
        RECT 573.350 0.010 578.950 0.560 ;
        RECT 579.790 0.010 585.390 0.560 ;
        RECT 586.230 0.010 591.830 0.560 ;
        RECT 592.670 0.010 598.270 0.560 ;
        RECT 599.110 0.010 604.710 0.560 ;
        RECT 605.550 0.010 611.150 0.560 ;
        RECT 611.990 0.010 617.590 0.560 ;
        RECT 618.430 0.010 624.030 0.560 ;
        RECT 624.870 0.010 630.470 0.560 ;
        RECT 631.310 0.010 636.910 0.560 ;
        RECT 637.750 0.010 643.350 0.560 ;
        RECT 644.190 0.010 649.790 0.560 ;
        RECT 650.630 0.010 656.230 0.560 ;
        RECT 657.070 0.010 662.670 0.560 ;
        RECT 663.510 0.010 669.110 0.560 ;
        RECT 669.950 0.010 675.550 0.560 ;
        RECT 676.390 0.010 681.990 0.560 ;
        RECT 682.830 0.010 687.150 0.560 ;
      LAYER met3 ;
        RECT 12.025 644.320 688.015 688.325 ;
        RECT 12.025 52.680 687.615 644.320 ;
        RECT 12.025 10.715 688.015 52.680 ;
      LAYER met4 ;
        RECT 16.855 19.895 20.640 643.105 ;
        RECT 23.040 19.895 23.940 643.105 ;
        RECT 26.340 19.895 174.240 643.105 ;
        RECT 176.640 19.895 177.540 643.105 ;
        RECT 179.940 19.895 327.840 643.105 ;
        RECT 330.240 19.895 331.140 643.105 ;
        RECT 333.540 19.895 481.440 643.105 ;
        RECT 483.840 19.895 484.740 643.105 ;
        RECT 487.140 19.895 593.105 643.105 ;
  END
END fec_wrapper
END LIBRARY

